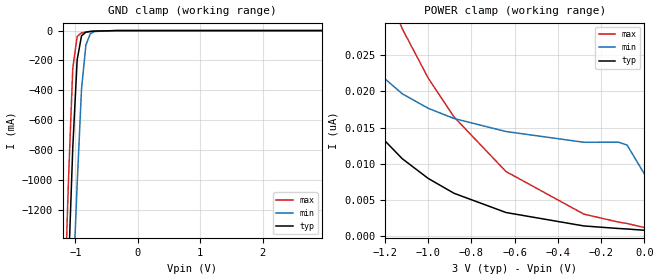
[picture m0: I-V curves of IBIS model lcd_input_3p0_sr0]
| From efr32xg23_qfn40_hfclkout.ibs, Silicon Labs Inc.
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|   Model lcd_input_3p0_sr0
[Model]  lcd_input_3p0_sr0
Model_type Input
C_comp   1.6300pF   1.4000pF   2.7000pF
[Temperature Range]   25.0000   0.1250k   -40.0000
[Pullup Reference]   3.0000V   2.7000V   3.3000V
[Pulldown Reference]   0.0V   0.0V   0.0V
[POWER Clamp Reference]   3.0000V   2.7000V   3.3000V
[GND Clamp Reference]   0.0V   0.0V   0.0V
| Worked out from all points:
|   GND clamp passes 1 mA (typ) near -0.56 V on its own axis
[GND_clamp]
|Voltage   I(typ)   I(min)   I(max)
-3V       -24.27A    -21.95A    -26.57A
-1.18V    -2.447A    -3.183A    -1.952A
-1.11V    -1.614A    -2.464A    -1.015A
-1.04V    -784mA     -1.746A    -252.8mA
-970mV    -196.2mA   -1.031A    -40.03mA
-900mV    -35mA      -390.7mA   -14.95mA
-830mV    -10.34mA   -96.94mA   -9.948mA
-760mV    -5.711mA   -21.43mA   -6.561mA
-690mV    -3.47mA    -6.05mA    -3.879mA
-340mV    -10.36uA   -45.49uA   -3.3uA
2.95V     657.9pA    12.89nA    538.5pA
[POWER_clamp]
|Voltage   I(typ)   I(min)   I(max)
-3V       338.2nA    9.288uA    587.2nA
-1.56V    29.18nA    39.44nA    70.52nA
-1.4V     20.57nA    28.74nA    51.74nA
-1.28V    15.63nA    23.83nA    40.5nA
-1.12V    10.68nA    19.68nA    28.7nA
-1V       7.945nA    17.67nA    21.86nA
-880mV    5.879nA    16.25nA    16.45nA
-640mV    3.219nA    14.45nA    8.897nA
-280mV    1.357nA    12.96nA    2.997nA
-120mV    1.003nA    12.97nA    1.894nA
-80mV     936.4pA    12.58nA    1.698nA
0V        757.3pA    8.576nA    1.134nA
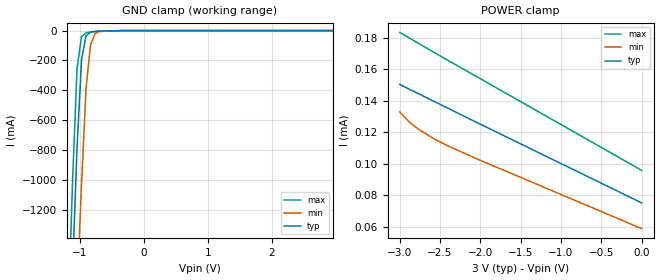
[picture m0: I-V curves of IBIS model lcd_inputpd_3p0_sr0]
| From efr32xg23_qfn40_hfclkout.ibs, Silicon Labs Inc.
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|   Model lcd_inputpd_3p0_sr0
[Model]  lcd_inputpd_3p0_sr0
Model_type Input
C_comp   1.6300pF   1.4000pF   2.7000pF
[Temperature Range]   25.0000   0.1250k   -40.0000
[Pullup Reference]   3.0000V   2.7000V   3.3000V
[Pulldown Reference]   0.0V   0.0V   0.0V
[POWER Clamp Reference]   3.0000V   2.7000V   3.3000V
[GND Clamp Reference]   0.0V   0.0V   0.0V
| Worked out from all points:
|   GND clamp passes 1 mA (typ) near -0.56 V on its own axis
[GND_clamp]
|Voltage   I(typ)   I(min)   I(max)
-3V       -24.27A    -21.95A    -26.57A
-1.18V    -2.447A    -3.183A    -1.952A
-1.11V    -1.614A    -2.464A    -1.015A
-1.04V    -784mA     -1.746A    -252.8mA
-970mV    -196.2mA   -1.031A    -40.04mA
-900mV    -35.01mA   -390.8mA   -14.96mA
-830mV    -10.35mA   -96.95mA   -9.963mA
-760mV    -5.723mA   -21.44mA   -6.576mA
-690mV    -3.482mA   -6.059mA   -3.893mA
-340mV    -18.62uA   -52.31uA   -13.01uA
2.95V     73.77uA    64.09uA    85.54uA
[POWER_clamp]
|Voltage   I(typ)   I(min)   I(max)
-3V       150.3uA    132.8uA    183.3uA
-2.88V    147.2uA    126.3uA    179.7uA
-2.76V    144.2uA    121.5uA    176.1uA
-2.56V    139.1uA    115.3uA    170.2uA
-2.4V     135.1uA    111.2uA    165.5uA
-2.08V    127uA      103.8uA    156.2uA
0V        75.02uA    58.67uA    95.69uA
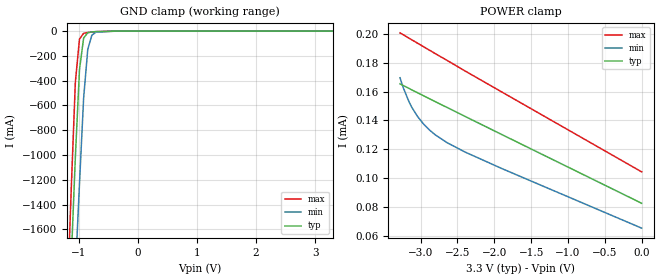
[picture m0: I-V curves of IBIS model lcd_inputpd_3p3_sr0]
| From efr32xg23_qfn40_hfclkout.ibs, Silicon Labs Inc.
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|   Model lcd_inputpd_3p3_sr0
[Model]  lcd_inputpd_3p3_sr0
Model_type Input
C_comp   1.6300pF   1.4000pF   2.7000pF
[Temperature Range]   25.0000   0.1250k   -40.0000
[Pullup Reference]   3.3000V   3.0000V   3.6000V
[Pulldown Reference]   0.0V   0.0V   0.0V
[POWER Clamp Reference]   3.3000V   3.0000V   3.6000V
[GND Clamp Reference]   0.0V   0.0V   0.0V
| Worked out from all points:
|   GND clamp passes 1 mA (typ) near -0.56 V on its own axis
[GND_clamp]
|Voltage   I(typ)   I(min)   I(max)
-3.3V     -27.87A    -25.05A    -30.64A
-1.2V     -2.686A    -3.389A    -2.22A
-1.13V    -1.852A    -2.669A    -1.282A
-1.06V    -1.021A    -1.951A    -413.8mA
-990mV    -311.8mA   -1.235A    -64.73mA
-920mV    -56.27mA   -542.5mA   -17.81mA
-850mV    -13.46mA   -148.6mA   -11.1mA
-780mV    -6.603mA   -32.69mA   -7.471mA
-710mV    -4.041mA   -8.332mA   -4.588mA
-360mV    -27.55uA   -77.14uA   -17.02uA
3.3V      82.64uA    71.93uA    95.72uA
[POWER_clamp]
|Voltage   I(typ)   I(min)   I(max)
-3.28V    165.4uA    169.6uA    200.7uA
-3.24V    164.3uA    163.2uA    199.5uA
-3.16V    162.3uA    153.2uA    197.1uA
-3.12V    161.2uA    149.1uA    195.9uA
-3.04V    159.2uA    142.6uA    193.5uA
-2.96V    157.1uA    137.5uA    191.1uA
-2.88V    155.1uA    133.4uA    188.7uA
-2.8V     153uA      130uA      186.3uA
-2.64V    149uA      124.6uA    181.6uA
-2.4V     142.9uA    118.2uA    174.4uA
-1.88V    129.8uA    106.3uA    159.2uA
0V        82.64uA    65.4uA     104.4uA
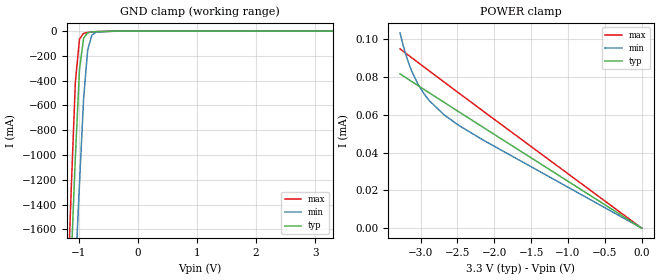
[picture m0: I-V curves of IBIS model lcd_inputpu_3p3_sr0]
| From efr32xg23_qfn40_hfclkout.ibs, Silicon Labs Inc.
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|   Model lcd_inputpu_3p3_sr0
[Model]  lcd_inputpu_3p3_sr0
Model_type Input
C_comp   1.6300pF   1.4000pF   2.7000pF
[Temperature Range]   25.0000   0.1250k   -40.0000
[Pullup Reference]   3.3000V   3.0000V   3.6000V
[Pulldown Reference]   0.0V   0.0V   0.0V
[POWER Clamp Reference]   3.3000V   3.0000V   3.6000V
[GND Clamp Reference]   0.0V   0.0V   0.0V
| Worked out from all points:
|   GND clamp passes 1 mA (typ) near -0.55 V on its own axis
[GND_clamp]
|Voltage   I(typ)   I(min)   I(max)
-3.3V     -27.87A    -25.05A    -30.64A
-1.2V     -2.686A    -3.389A    -2.22A
-1.13V    -1.852A    -2.669A    -1.282A
-1.06V    -1.021A    -1.951A    -413.9mA
-990mV    -311.9mA   -1.235A    -64.84mA
-920mV    -56.35mA   -542.5mA   -17.92mA
-850mV    -13.55mA   -148.6mA   -11.2mA
-780mV    -6.685mA   -32.76mA   -7.575mA
-710mV    -4.123mA   -8.397mA   -4.692mA
-360mV    -109.6uA   -142.3uA   -120.6uA
3.3V      1.052nA    6.53uA     -8.645uA
[POWER_clamp]
|Voltage   I(typ)   I(min)   I(max)
-3.28V    81.7uA     103.4uA    94.94uA
-3.24V    80.68uA    97.09uA    93.76uA
-3.2V     79.66uA    91.69uA    92.58uA
-3.16V    78.64uA    87.06uA    91.4uA
-3.12V    77.62uA    83.05uA    90.22uA
-3.04V    75.6uA     76.51uA    87.87uA
-2.96V    73.59uA    71.45uA    85.52uA
-2.88V    71.58uA    67.4uA     83.18uA
-2.68V    66.57uA    59.94uA    77.33uA
-2.48V    61.58uA    54.37uA    71.5uA
-2.16V    53.61uA    46.83uA    62.22uA
0V        1.052nA    8.934nA    2.227nA
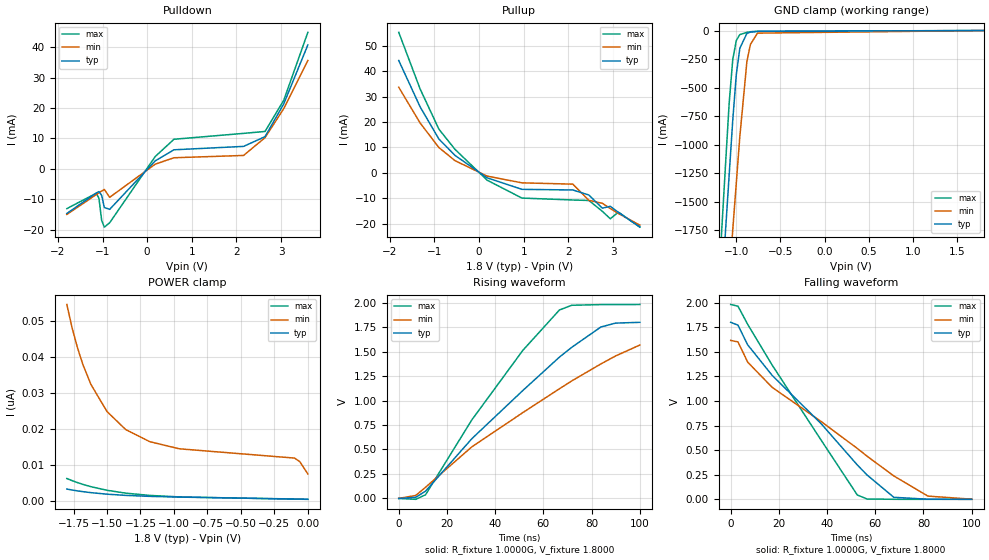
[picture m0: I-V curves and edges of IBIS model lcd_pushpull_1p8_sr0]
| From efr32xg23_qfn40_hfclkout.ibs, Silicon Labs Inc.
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|   Model lcd_pushpull_1p8_sr0
[Model]  lcd_pushpull_1p8_sr0
Model_type 3-state
Polarity   Non-Inverting
Enable   Active-High
C_comp   1.6300pF   1.4000pF   2.7000pF
[Temperature Range]   25.0000   0.1250k   -40.0000
[Pullup Reference]   1.8000V   1.6200V   1.9800V
[Pulldown Reference]   0.0V   0.0V   0.0V
[POWER Clamp Reference]   1.8000V   1.6200V   1.9800V
[GND Clamp Reference]   0.0V   0.0V   0.0V
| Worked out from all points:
|   slope of the pulldown table from 0 to 0.27 V, typ, clamps not added: 73.7 ohm
|   slope of the pullup table from 0 to 0.27 V, typ, clamps not added: 94.5 ohm
|   GND clamp passes 1 mA (typ) near -0.56 V on its own axis
|   rising waveform, R_fixture 1.0000G, V_fixture 1.8000: 20-80 % time 44.8ns typ, 55.5ns min, 33.5ns max; typ from 0 V to 1.8 V
|   falling waveform, R_fixture 1.0000G, V_fixture 1.8000: 20-80 % time 41.1ns typ, 52.2ns min, 30.7ns max; typ from 1.8 V to 0 V
[Pulldown]
|Voltage   I(typ)   I(min)   I(max)
-1.8V     -14.7mA    -15.01mA   -13.1mA
-1.14V    -7.95mA    -8.476mA   -8.033mA
-1.08V    -7.493mA   -7.885mA   -9.701mA
-1.02V    -8.713mA   -7.306mA   -16.93mA
-960mV    -12.74mA   -6.774mA   -19.2mA
-840mV    -13.34mA   -9.372mA   -17.75mA
180mV     2.62mA     1.539mA    4.045mA
600mV     6.272mA    3.652mA    9.739mA
2.16V     7.393mA    4.409mA    11.68mA
2.64V     10.59mA    10.27mA    12.31mA
3.06V     21.4mA     19.84mA    22.59mA
3.6V      40.81mA    35.67mA    44.95mA
[Pullup]
|Voltage   I(typ)   I(min)   I(max)
-1.8V     44.26mA    33.72mA    55.37mA
-1.32V    25.95mA    19.61mA    32.99mA
-900mV    13.3mA     9.934mA    17.18mA
-540mV    6.86mA     4.786mA    9.239mA
180mV     -2.006mA   -1.315mA   -2.92mA
960mV     -6.533mA   -3.97mA    -9.976mA
2.1V      -6.782mA   -4.481mA   -10.73mA
2.46V     -8.779mA   -10.88mA   -10.92mA
2.76V     -13.95mA   -12.02mA   -15.17mA
2.94V     -13.22mA   -14.09mA   -18.14mA
3.12V     -15.62mA   -16.06mA   -15.5mA
3.6V      -21.33mA   -20.63mA   -21.44mA
[GND_clamp]
|Voltage   I(typ)   I(min)   I(max)
-1.8V     -9.867A    -9.569A    -10.32A
-1.2V     -2.688A    -3.389A    -2.223A
-1.16V    -2.211A    -2.978A    -1.687A
-1.12V    -1.735A    -2.567A    -1.152A
-1.08V    -1.26A     -2.157A    -630.3mA
-1.04V    -786.2mA   -1.747A    -256.2mA
-1V       -388.1mA   -1.338A    -87.58mA
-960mV    -155.8mA   -930mA     -35.74mA
-880mV    -25.03mA   -272.7mA   -16.29mA
-840mV    -13.92mA   -121.5mA   -10.46mA
-760mV    -7.819mA   -22.78mA   -6.532mA
1.8V      420.7pA    11.94nA    334.2pA
[POWER_clamp]
|Voltage   I(typ)   I(min)   I(max)
-1.8V     3.26nA     54.56nA    6.193nA
-1.76V    2.991nA    47.98nA    5.591nA
-1.72V    2.751nA    42.48nA    5.048nA
-1.68V    2.538nA    37.87nA    4.559nA
-1.62V    2.261nA    32.33nA    3.919nA
-1.5V     1.836nA    24.81nA    2.92nA
-1.36V    1.5nA      19.78nA    2.12nA
-1.18V    1.228nA    16.42nA    1.491nA
-960mV    1.023nA    14.45nA    1.076nA
-100mV    499.2pA    11.87nA    445.7pA
-60mV     472.6pA    10.86nA    433.4pA
0V        420.7pA    7.448nA    403.8pA
[Ramp]
| variable   typ   min   max
dV/dt_r  1.0333/48.1802n   0.8058/54.3189n   1.1719/36.3741n
dV/dt_f  1.0636/46.4446n   0.9166/59.9076n   1.1807/33.5893n
R_load = 10.0000k
[Rising Waveform]
R_fixture= 1.0000G
V_fixture= 1.8000
V_fixture_min= 1.6200
V_fixture_max= 1.9800
|time   V(typ)   V(min)   V(max)
0s        347uV      809.6uV    128.9uV
7.071ns   12.12mV    31.05mV    -8.769mV
11.11ns   74.53mV    114.2mV    37.75mV
30.3ns    609.7mV    526.6mV    801.3mV
51.52ns   1.103V     877.3mV    1.513V
66.67ns   1.443V     1.12V      1.924V
71.72ns   1.542V     1.199V     1.972V
83.84ns   1.75V      1.373V     1.979V
89.9ns    1.79V      1.454V     1.979V
100ns     1.798V     1.566V     1.98V
[Falling Waveform]
R_fixture= 1.0000G
V_fixture= 1.8000
V_fixture_min= 1.6200
V_fixture_max= 1.9800
|time   V(typ)   V(min)   V(max)
0s        1.799V     1.615V     1.98V
3.03ns    1.77V      1.6V       1.963V
7.071ns   1.57V      1.394V     1.778V
17.17ns   1.261V     1.139V     1.366V
37.37ns   773.3mV    793.6mV    607.7mV
52.53ns   349.9mV    517.6mV    44.53mV
56.57ns   247.8mV    439mV      3.564mV
67.68ns   20.81mV    238.1mV    555.3uV
81.82ns   1.007mV    33.01mV    259.7uV
100ns     383.8uV    1.598mV    130.2uV
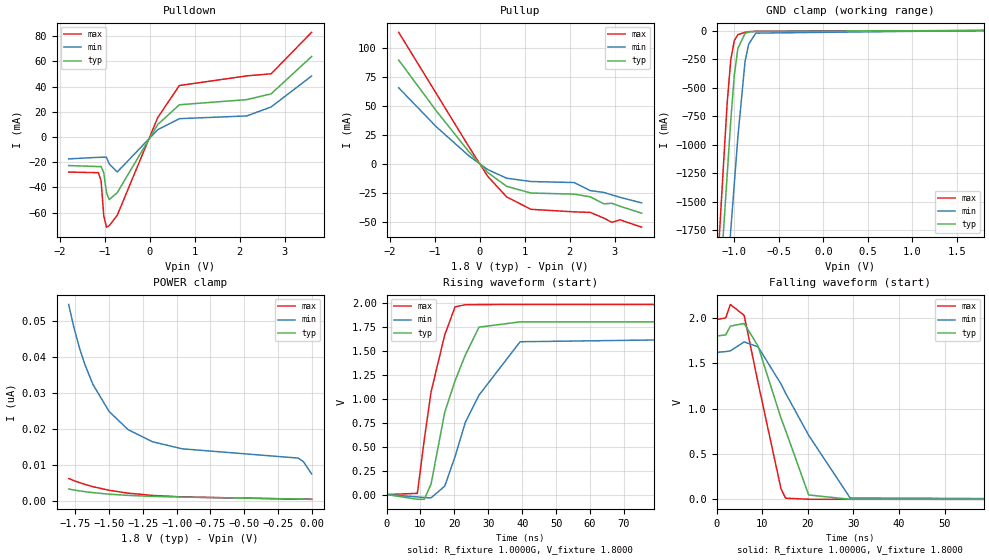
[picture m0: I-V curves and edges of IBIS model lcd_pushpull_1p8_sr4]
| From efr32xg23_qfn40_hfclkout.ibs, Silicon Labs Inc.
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|   Model lcd_pushpull_1p8_sr4
[Model]  lcd_pushpull_1p8_sr4
Model_type 3-state
Polarity   Non-Inverting
Enable   Active-High
C_comp   1.6300pF   1.4000pF   2.7000pF
[Temperature Range]   25.0000   0.1250k   -40.0000
[Pullup Reference]   1.8000V   1.6200V   1.9800V
[Pulldown Reference]   0.0V   0.0V   0.0V
[POWER Clamp Reference]   1.8000V   1.6200V   1.9800V
[GND Clamp Reference]   0.0V   0.0V   0.0V
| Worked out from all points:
|   slope of the pulldown table from 0 to 0.27 V, typ, clamps not added: 19.4 ohm
|   slope of the pullup table from 0 to 0.27 V, typ, clamps not added: 26.3 ohm
|   GND clamp passes 1 mA (typ) near -0.56 V on its own axis
|   rising waveform, R_fixture 1.0000G, V_fixture 1.8000: 20-80 % time 8.5ns typ, 12.4ns min, 5.99ns max; typ from 0 V to 1.8 V
|   falling waveform, R_fixture 1.0000G, V_fixture 1.8000: 20-80 % time 7.02ns typ, 10.4ns min, 4.86ns max; typ from 1.8 V to 0 V
[Pulldown]
|Voltage   I(typ)   I(min)   I(max)
-1.8V     -22.72mA   -17.46mA   -27.89mA
-1.14V    -23.53mA   -16.18mA   -28.38mA
-1.08V    -23.42mA   -16.18mA   -34.7mA
-1.02V    -28.53mA   -16.15mA   -62.46mA
-960mV    -44.06mA   -16.13mA   -71.6mA
-900mV    -49.75mA   -21.38mA   -70.47mA
-720mV    -44.21mA   -27.82mA   -62.15mA
180mV     9.861mA    5.736mA    15.36mA
660mV     25.51mA    14.47mA    40.77mA
2.16V     29.61mA    16.66mA    48.44mA
2.7V      34.16mA    23.78mA    50.07mA
3.6V      63.79mA    48.31mA    82.99mA
[Pullup]
|Voltage   I(typ)   I(min)   I(max)
-1.8V     89.55mA    65.7mA     113.4mA
-960mV    45.65mA    32.03mA    60.52mA
-240mV    10.71mA    7.201mA    15.05mA
180mV     -7.21mA    -4.712mA   -10.49mA
600mV     -19.07mA   -12.08mA   -28.15mA
1.14V     -24.85mA   -14.93mA   -38.85mA
2.1V      -25.76mA   -15.8mA    -41.02mA
2.46V     -28.12mA   -22.77mA   -41.5mA
2.76V     -34.11mA   -24.28mA   -46.4mA
2.94V     -33.67mA   -26.45mA   -50.04mA
3.12V     -36.21mA   -28.52mA   -47.86mA
3.6V      -42.18mA   -33.32mA   -54.18mA
[GND_clamp]
|Voltage   I(typ)   I(min)   I(max)
-1.8V     -9.867A    -9.569A    -10.32A
-1.2V     -2.688A    -3.389A    -2.223A
-1.16V    -2.211A    -2.978A    -1.687A
-1.12V    -1.735A    -2.567A    -1.152A
-1.08V    -1.26A     -2.157A    -630.3mA
-1.04V    -786.2mA   -1.747A    -256.2mA
-1V       -388.1mA   -1.338A    -87.58mA
-960mV    -155.8mA   -930mA     -35.74mA
-880mV    -25.03mA   -272.7mA   -16.29mA
-840mV    -13.92mA   -121.5mA   -10.46mA
-760mV    -7.819mA   -22.78mA   -6.532mA
1.8V      420.7pA    11.94nA    334.2pA
[POWER_clamp]
|Voltage   I(typ)   I(min)   I(max)
-1.8V     3.26nA     54.56nA    6.193nA
-1.76V    2.991nA    47.98nA    5.591nA
-1.72V    2.751nA    42.48nA    5.048nA
-1.68V    2.538nA    37.87nA    4.559nA
-1.62V    2.261nA    32.33nA    3.919nA
-1.5V     1.836nA    24.81nA    2.92nA
-1.36V    1.5nA      19.78nA    2.12nA
-1.18V    1.228nA    16.42nA    1.491nA
-960mV    1.023nA    14.45nA    1.076nA
-100mV    499.2pA    11.87nA    445.7pA
-60mV     472.6pA    10.86nA    433.4pA
0V        420.7pA    7.448nA    403.8pA
[Ramp]
| variable   typ   min   max
dV/dt_r  1.0772/9.0593n   0.9679/13.5624n   1.1859/6.2617n
dV/dt_f  1.0782/7.3523n   0.9692/11.1155n   1.1867/5.0016n
R_load = 10.0000k
[Rising Waveform]
R_fixture= 1.0000G
V_fixture= 1.8000
V_fixture_min= 1.6200
V_fixture_max= 1.9800
|time   V(typ)   V(min)   V(max)
0s        6.707uV    22.16uV    2.837uV
9.091ns   -49.63mV   -24.87mV   12.25mV
11.11ns   -49.96mV   -31.4mV    567mV
13.13ns   108.3mV    -34.57mV   1.069V
17.17ns   858.5mV    87.45mV    1.664V
20.2ns    1.185V     394.7mV    1.955V
23.23ns   1.453V     751.7mV    1.978V
27.27ns   1.744V     1.036V     1.979V
39.39ns   1.799V     1.592V     1.98V
100ns     1.8V       1.62V      1.98V
[Falling Waveform]
R_fixture= 1.0000G
V_fixture= 1.8000
V_fixture_min= 1.6200
V_fixture_max= 1.9800
|time   V(typ)   V(min)   V(max)
0s        1.8V       1.62V      1.98V
2.02ns    1.812V     1.628V     2V
3.03ns    1.909V     1.636V     2.147V
6.061ns   1.938V     1.735V     2.027V
9.091ns   1.69V      1.681V     1.288V
14.14ns   893.2mV    1.271V     114.9mV
15.15ns   758.6mV    1.169V     12.83mV
20.2ns    47.98mV    705.9mV    510.2uV
29.29ns   507.4uV    15.11mV    137.5uV
100ns     6.843uV    22.31uV    2.847uV
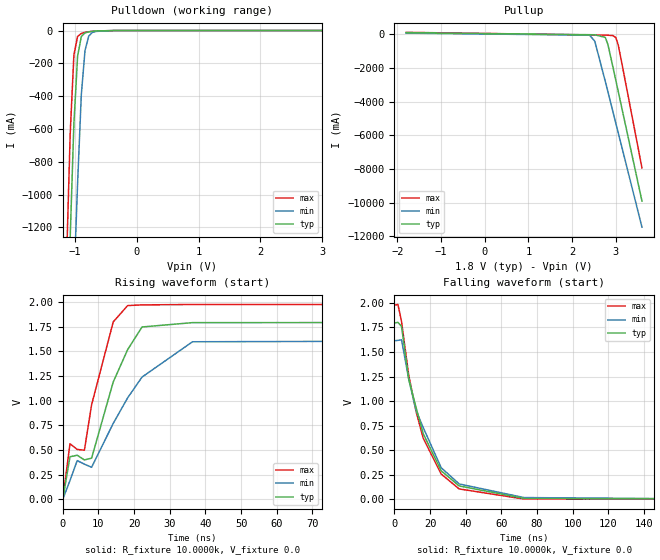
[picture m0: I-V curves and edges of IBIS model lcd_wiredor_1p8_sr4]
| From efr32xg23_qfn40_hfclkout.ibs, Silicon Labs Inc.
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|   Model lcd_wiredor_1p8_sr4
[Model]  lcd_wiredor_1p8_sr4
Model_type Output
Polarity   Non-Inverting
Enable   Active-Low
C_comp   1.6300pF   1.4000pF   2.7000pF
[Temperature Range]   25.0000   0.1250k   -40.0000
[Pullup Reference]   1.8000V   1.6200V   1.9800V
[Pulldown Reference]   0.0V   0.0V   0.0V
[POWER Clamp Reference]   1.8000V   1.6200V   1.9800V
[GND Clamp Reference]   0.0V   0.0V   0.0V
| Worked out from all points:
|   slope of the pullup table from 0 to 0.27 V, typ, clamps not added: 26.3 ohm
|   rising waveform, R_fixture 10.0000k, V_fixture 0.0: 20-80 % time 15.4ns typ, 20ns min, 10.9ns max; typ from 0 V to 1.79 V
|   falling waveform, R_fixture 10.0000k, V_fixture 0.0: 20-80 % time 17.3ns typ, 18.7ns min, 15.9ns max; typ from 1.8 V to 0 V
[Pulldown]
|Voltage   I(typ)   I(min)   I(max)
-1.8V     -9.867A    -9.569A    -10.32A
-1.14V    -1.973A    -2.773A    -1.419A
-1.08V    -1.26A     -2.157A    -630.4mA
-1.02V    -568mA     -1.543A    -149.7mA
-960mV    -155.8mA   -930mA     -35.74mA
-900mV    -37.3mA    -392mA     -18.17mA
-840mV    -13.92mA   -121.5mA   -10.46mA
-780mV    -8.725mA   -34.03mA   -7.422mA
-720mV    -4.294mA   -11.21mA   -4.92mA
-660mV    -2.711mA   -5.267mA   -2.939mA
-360mV    -18.79uA   -69.64uA   -6.715uA
3.6V      3.264nA    104.4nA    3.919nA
[Pullup]
|Voltage   I(typ)   I(min)   I(max)
-1.8V     89.55mA    65.7mA     113.4mA
2.4V      -28.79mA   -55.09mA   -41.35mA
2.52V     -33.4mA    -414.8mA   -42.59mA
2.76V     -189.9mA   -2.797A    -53.83mA
2.82V     -601mA     -3.414A    -58.12mA
2.94V     -2.006A    -4.65A     -82.38mA
3V        -2.722A    -5.268A    -196.6mA
3.06V     -3.439A    -5.887A    -675.1mA
3.12V     -4.156A    -6.505A    -1.464A
3.24V     -5.593A    -7.743A    -3.076A
3.3V      -6.312A    -8.362A    -3.885A
3.6V      -9.909A    -11.46A    -7.939A
[Ramp]
| variable   typ   min   max
dV/dt_r  1.0773/15.4419n   0.9682/19.9658n   1.1859/10.8682n
dV/dt_f  47.8332u/2.7967p   38.5697u/5.0330p   85.2176u/2.8246p
R_load = 10.0000k
[Rising Waveform]
R_fixture= 10.0000k
V_fixture= 0.0
V_fixture_min= 0.0
V_fixture_max= 0.0
|time   V(typ)   V(min)   V(max)
0s        3.312uV    55.57uV    2.87uV
2.02ns    431.5mV    190.6mV    564mV
4.04ns    447.3mV    392.9mV    505.8mV
6.061ns   399.6mV    356.7mV    498.5mV
8.081ns   417.6mV    325.2mV    958.9mV
14.14ns   1.19V      769.9mV    1.799V
18.18ns   1.518V     1.029V     1.965V
22.22ns   1.748V     1.24V      1.972V
36.36ns   1.792V     1.598V     1.976V
200ns     1.795V     1.614V     1.976V
[Falling Waveform]
R_fixture= 10.0000k
V_fixture= 0.0
V_fixture_min= 0.0
V_fixture_max= 0.0
|time   V(typ)   V(min)   V(max)
0s        1.796V     1.614V     1.977V
2.02ns    1.802V     1.619V     1.984V
4.04ns    1.761V     1.624V     1.809V
8.081ns   1.224V     1.222V     1.262V
12.12ns   938.8mV    906.8mV    899mV
16.16ns   669.5mV    732.2mV    623.1mV
26.26ns   290.1mV    321.8mV    257.2mV
36.36ns   135.8mV    156.1mV    105.4mV
72.73ns   8.787mV    17.35mV    2.315mV
200ns     -102.6uV   786.2uV    -490.8uV
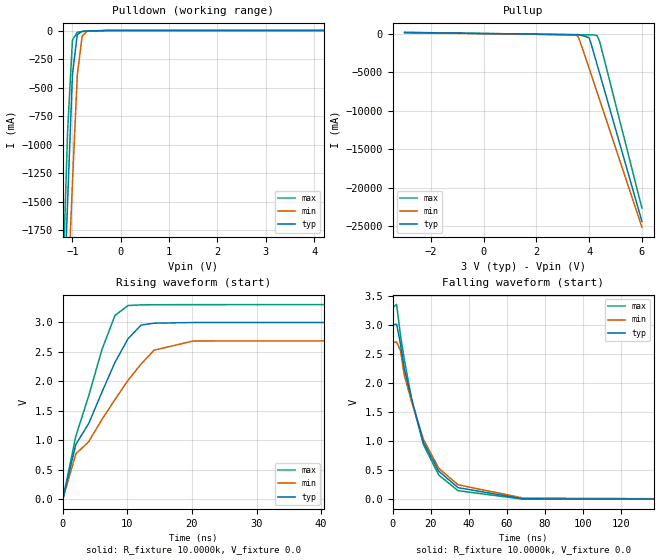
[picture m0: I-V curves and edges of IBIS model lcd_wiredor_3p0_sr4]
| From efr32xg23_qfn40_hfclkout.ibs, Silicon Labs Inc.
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|   Model lcd_wiredor_3p0_sr4
[Model]  lcd_wiredor_3p0_sr4
Model_type Output
Polarity   Non-Inverting
Enable   Active-Low
C_comp   1.6300pF   1.4000pF   2.7000pF
[Temperature Range]   25.0000   0.1250k   -40.0000
[Pullup Reference]   3.0000V   2.7000V   3.3000V
[Pulldown Reference]   0.0V   0.0V   0.0V
[POWER Clamp Reference]   3.0000V   2.7000V   3.3000V
[GND Clamp Reference]   0.0V   0.0V   0.0V
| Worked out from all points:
|   slope of the pullup table from 0 to 0.45 V, typ, clamps not added: 16.9 ohm
|   rising waveform, R_fixture 10.0000k, V_fixture 0.0: 20-80 % time 7.17ns typ, 9.72ns min, 5.18ns max; typ from 0 V to 3 V
|   falling waveform, R_fixture 10.0000k, V_fixture 0.0: 20-80 % time 16.5ns typ, 18.1ns min, 14.8ns max; typ from 3 V to 0 V
[Pulldown]
|Voltage   I(typ)   I(min)   I(max)
-3V       -24.27A    -21.95A    -26.57A
-1.2V     -2.686A    -3.389A    -2.22A
-1.1V     -1.495A    -2.361A    -881.8mA
-1V       -385.8mA   -1.337A    -84.19mA
-900mV    -34.99mA   -390.7mA   -14.95mA
-800mV    -7.703mA   -50.4mA    -8.403mA
-700mV    -3.742mA   -7.062mA   -4.219mA
-300mV    -2.847uA   -17.98uA   -692.6nA
6V        338.2nA    35.99uA    408.8nA
[Pullup]
|Voltage   I(typ)   I(min)   I(max)
-3V       194.2mA    164.1mA    218.3mA
3.5V      -78.04mA   -106.9mA   -111.5mA
3.6V      -80.27mA   -448.8mA   -111.7mA
4V        -471.9mA   -4.48A     -119.8mA
4.1V      -1.581A    -5.511A    -126.2mA
4.2V      -2.773A    -6.543A    -134.9mA
4.3V      -3.971A    -7.574A    -205.9mA
4.4V      -5.168A    -8.607A    -1.001A
4.5V      -6.366A    -9.639A    -2.34A
4.7V      -8.765A    -11.71A    -5.039A
4.8V      -9.964A    -12.74A    -6.39A
6V        -24.38A    -25.14A    -22.65A
[Ramp]
| variable   typ   min   max
dV/dt_r  1.7971/7.1745n   1.6163/9.7176n   1.9776/5.1781n
dV/dt_f  0.1145m/6.6608p   65.9331u/5.4080p   0.2003m/5.3495p
R_load = 10.0000k
[Rising Waveform]
R_fixture= 10.0000k
V_fixture= 0.0
V_fixture_min= 0.0
V_fixture_max= 0.0
|time   V(typ)   V(min)   V(max)
0s        4.624uV    47.91uV    4.748uV
2.02ns    929mV      768mV      1.068V
4.04ns    1.288V     979.6mV    1.761V
6.061ns   1.813V     1.352V     2.532V
8.081ns   2.318V     1.687V     3.112V
10.1ns    2.716V     2.014V     3.279V
12.12ns   2.947V     2.289V     3.289V
14.14ns   2.98V      2.523V     3.292V
20.2ns    2.991V     2.679V     3.294V
200ns     2.995V     2.694V     3.296V
[Falling Waveform]
R_fixture= 10.0000k
V_fixture= 0.0
V_fixture_min= 0.0
V_fixture_max= 0.0
|time   V(typ)   V(min)   V(max)
0s        2.995V     2.694V     3.296V
2.02ns    3.01V      2.704V     3.347V
4.04ns    2.67V      2.557V     2.819V
6.061ns   2.24V      2.134V     2.406V
10.1ns    1.704V     1.655V     1.684V
16.16ns   975.7mV    1.029V     936mV
24.24ns   482.9mV    530.6mV    415.7mV
34.34ns   199.8mV    249.4mV    148.3mV
68.69ns   8.115mV    21.09mV    1.351mV
200ns     -452.2uV   289.4uV    -558.8uV
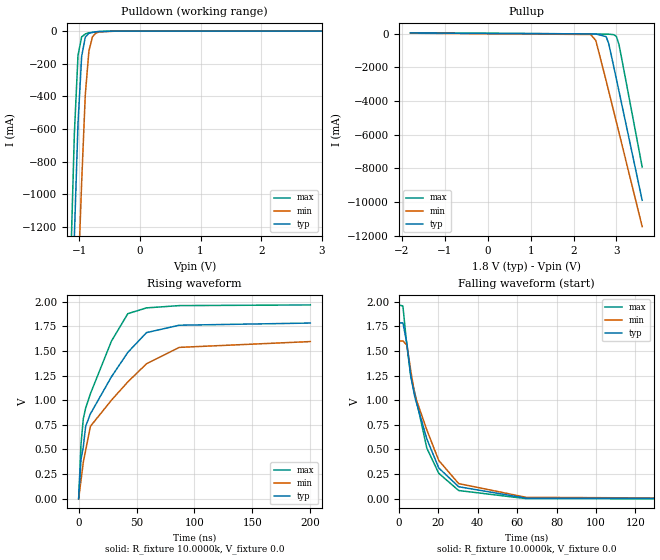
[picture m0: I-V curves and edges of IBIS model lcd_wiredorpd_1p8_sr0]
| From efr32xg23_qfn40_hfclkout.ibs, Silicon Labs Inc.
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|   Model lcd_wiredorpd_1p8_sr0
[Model]  lcd_wiredorpd_1p8_sr0
Model_type Output
Polarity   Non-Inverting
Enable   Active-Low
C_comp   1.6300pF   1.4000pF   2.7000pF
[Temperature Range]   25.0000   0.1250k   -40.0000
[Pullup Reference]   1.8000V   1.6200V   1.9800V
[Pulldown Reference]   0.0V   0.0V   0.0V
[POWER Clamp Reference]   1.8000V   1.6200V   1.9800V
[GND Clamp Reference]   0.0V   0.0V   0.0V
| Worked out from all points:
|   slope of the pulldown table from 0 to 0.27 V, typ, clamps not added: 40.6 kohm
|   slope of the pullup table from 0 to 0.27 V, typ, clamps not added: 94.5 ohm
|   rising waveform, R_fixture 10.0000k, V_fixture 0.0: 20-80 % time 37.1ns typ, 46.6ns min, 25.9ns max; typ from 0 V to 1.78 V
|   falling waveform, R_fixture 10.0000k, V_fixture 0.0: 20-80 % time 14ns typ, 15.9ns min, 12.5ns max; typ from 1.78 V to 0 V
[Pulldown]
|Voltage   I(typ)   I(min)   I(max)
-1.8V     -9.867A    -9.569A    -10.32A
-1.14V    -1.973A    -2.773A    -1.419A
-1.08V    -1.26A     -2.157A    -630.5mA
-1.02V    -568mA     -1.543A    -149.7mA
-960mV    -155.8mA   -930mA     -35.75mA
-900mV    -37.31mA   -392mA     -18.18mA
-840mV    -13.93mA   -121.5mA   -10.47mA
-780mV    -8.737mA   -34.04mA   -7.436mA
-720mV    -4.306mA   -11.22mA   -4.934mA
-660mV    -2.722mA   -5.276mA   -2.953mA
-360mV    -27.29uA   -76.51uA   -16.82uA
3.6V      88.26uA    75.14uA    103.4uA
[Pullup]
|Voltage   I(typ)   I(min)   I(max)
-1.8V     44.26mA    33.72mA    55.37mA
2.4V      -9.562mA   -43.33mA   -10.84mA
2.52V     -13.93mA   -402.8mA   -11.94mA
2.76V     -169.7mA   -2.785A    -22.6mA
2.82V     -580.7mA   -3.402A    -26.69mA
2.94V     -1.986A    -4.637A    -53.89mA
3V        -2.702A    -5.256A    -167.9mA
3.06V     -3.418A    -5.874A    -646.3mA
3.12V     -4.136A    -6.493A    -1.435A
3.24V     -5.572A    -7.731A    -3.047A
3.3V      -6.291A    -8.35A     -3.855A
3.6V      -9.889A    -11.45A    -7.908A
[Ramp]
| variable   typ   min   max
dV/dt_r  1.0697/37.0699n   0.9570/46.5903n   1.1803/25.8549n
dV/dt_f  0.2131/9.8036n   0.1690/11.4670n   0.2651/7.8311n
R_load = 10.0000k
[Rising Waveform]
R_fixture= 10.0000k
V_fixture= 0.0
V_fixture_min= 0.0
V_fixture_max= 0.0
|time   V(typ)   V(min)   V(max)
0s        2.578uV    44.87uV    2.149uV
2.02ns    397.7mV    185.1mV    553.4mV
4.04ns    528.4mV    373mV      813.5mV
6.061ns   736.8mV    491mV      920.7mV
10.1ns    860.4mV    733.8mV    1.064V
28.28ns   1.237V     1V         1.599V
42.42ns   1.485V     1.185V     1.878V
58.59ns   1.686V     1.37V      1.937V
86.87ns   1.761V     1.536V     1.96V
200ns     1.783V     1.595V     1.967V
[Falling Waveform]
R_fixture= 10.0000k
V_fixture= 0.0
V_fixture_min= 0.0
V_fixture_max= 0.0
|time   V(typ)   V(min)   V(max)
0s        1.785V     1.6V       1.968V
2.02ns    1.786V     1.603V     1.957V
4.04ns    1.577V     1.559V     1.553V
6.061ns   1.241V     1.295V     1.236V
8.081ns   1.032V     1.049V     1.073V
14.14ns   607.6mV    699.5mV    514.3mV
20.2ns    312.1mV    388.5mV    258.4mV
30.3ns    121.2mV    153.2mV    82.78mV
64.65ns   5.131mV    13.33mV    76.77uV
200ns     -87.29uV   582.2uV    -353.4uV
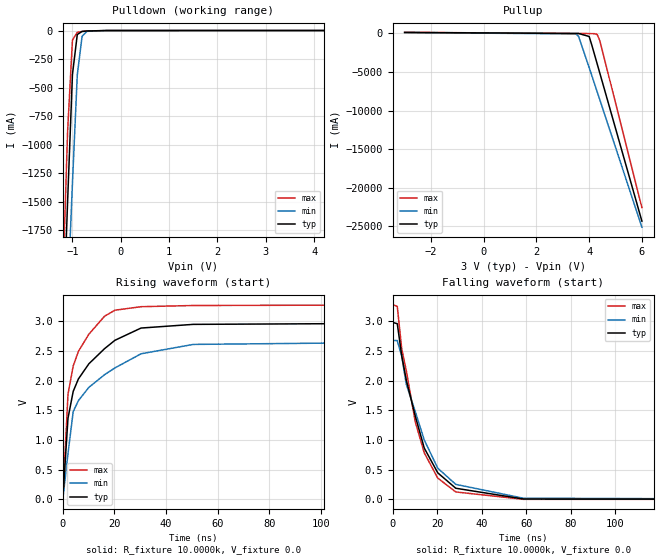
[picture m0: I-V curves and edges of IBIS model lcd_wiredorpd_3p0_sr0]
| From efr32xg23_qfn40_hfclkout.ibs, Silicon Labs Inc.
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|   Model lcd_wiredorpd_3p0_sr0
[Model]  lcd_wiredorpd_3p0_sr0
Model_type Output
Polarity   Non-Inverting
Enable   Active-Low
C_comp   1.6300pF   1.4000pF   2.7000pF
[Temperature Range]   25.0000   0.1250k   -40.0000
[Pullup Reference]   3.0000V   2.7000V   3.3000V
[Pulldown Reference]   0.0V   0.0V   0.0V
[POWER Clamp Reference]   3.0000V   2.7000V   3.3000V
[GND Clamp Reference]   0.0V   0.0V   0.0V
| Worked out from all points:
|   slope of the pulldown table from 0 to 0.45 V, typ, clamps not added: 40 kohm
|   slope of the pullup table from 0 to 0.45 V, typ, clamps not added: 61.2 ohm
|   rising waveform, R_fixture 10.0000k, V_fixture 0.0: 20-80 % time 11.4ns typ, 16.1ns min, 6.97ns max; typ from 0 V to 2.98 V
|   falling waveform, R_fixture 10.0000k, V_fixture 0.0: 20-80 % time 13.4ns typ, 14.8ns min, 11.8ns max; typ from 2.98 V to 0 V
[Pulldown]
|Voltage   I(typ)   I(min)   I(max)
-3V       -24.27A    -21.95A    -26.57A
-1.2V     -2.686A    -3.389A    -2.22A
-1.1V     -1.495A    -2.361A    -881.8mA
-1V       -385.8mA   -1.337A    -84.2mA
-900mV    -35.01mA   -390.8mA   -14.96mA
-800mV    -7.715mA   -50.41mA   -8.418mA
-700mV    -3.753mA   -7.071mA   -4.233mA
-300mV    -10.27uA   -24.2uA    -9.353uA
6V        150.3uA    165.9uA    174.4uA
[Pullup]
|Voltage   I(typ)   I(min)   I(max)
-3V       110.5mA    92.38mA    126.9mA
3.5V      -20.93mA   -70.49mA   -28.69mA
3.6V      -22.98mA   -412.2mA   -28.7mA
4V        -413.4mA   -4.443A    -35.97mA
4.1V      -1.522A    -5.474A    -42.03mA
4.2V      -2.714A    -6.505A    -50.3mA
4.3V      -3.912A    -7.537A    -120.8mA
4.4V      -5.109A    -8.569A    -915.3mA
4.5V      -6.307A    -9.602A    -2.255A
4.7V      -8.705A    -11.67A    -4.954A
4.8V      -9.905A    -12.7A     -6.304A
6V        -24.32A    -25.1A     -22.56A
[Ramp]
| variable   typ   min   max
dV/dt_r  1.7893/11.4345n   1.6058/16.1232n   1.9711/6.9728n
dV/dt_f  0.3602/8.6531n   0.2882/10.8504n   0.4453/7.7858n
R_load = 10.0000k
[Rising Waveform]
R_fixture= 10.0000k
V_fixture= 0.0
V_fixture_min= 0.0
V_fixture_max= 0.0
|time   V(typ)   V(min)   V(max)
0s        3.563uV    38.12uV    3.534uV
2.02ns    1.368V     771.5mV    1.773V
4.04ns    1.821V     1.479V     2.249V
6.061ns   2.031V     1.665V     2.496V
10.1ns    2.285V     1.888V     2.784V
16.16ns   2.54V      2.101V     3.087V
20.2ns    2.682V     2.216V     3.189V
30.3ns    2.888V     2.454V     3.248V
50.51ns   2.95V      2.612V     3.268V
200ns     2.982V     2.676V     3.285V
[Falling Waveform]
R_fixture= 10.0000k
V_fixture= 0.0
V_fixture_min= 0.0
V_fixture_max= 0.0
|time   V(typ)   V(min)   V(max)
0s        2.984V     2.679V     3.286V
2.02ns    2.962V     2.678V     3.253V
4.04ns    2.416V     2.409V     2.533V
6.061ns   2.013V     1.941V     2.172V
10.1ns    1.403V     1.479V     1.306V
14.14ns   863.8mV    1V         783.3mV
20.2ns    446.2mV    524.6mV    357.6mV
28.28ns   186.3mV    251.8mV    124mV
58.59ns   5.314mV    18.58mV    -604.8uV
200ns     -336.5uV   209.9uV    -398.3uV
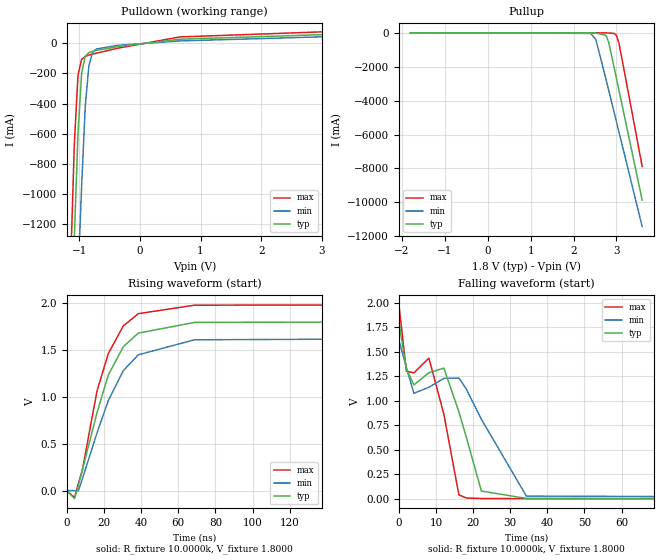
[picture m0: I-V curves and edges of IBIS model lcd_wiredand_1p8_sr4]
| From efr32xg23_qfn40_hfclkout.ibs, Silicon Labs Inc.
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|   Model lcd_wiredand_1p8_sr4
[Model]  lcd_wiredand_1p8_sr4
Model_type Output
Polarity   Inverting
Enable   Active-Low
C_comp   1.6300pF   1.4000pF   2.7000pF
[Temperature Range]   25.0000   0.1250k   -40.0000
[Pullup Reference]   1.8000V   1.6200V   1.9800V
[Pulldown Reference]   0.0V   0.0V   0.0V
[POWER Clamp Reference]   1.8000V   1.6200V   1.9800V
[GND Clamp Reference]   0.0V   0.0V   0.0V
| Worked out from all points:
|   slope of the pulldown table from 0 to 0.27 V, typ, clamps not added: 19.4 ohm
|   rising waveform, R_fixture 10.0000k, V_fixture 1.8000: 20-80 % time 16.8ns typ, 19.9ns min, 15ns max; typ from 0.003 V to 1.8 V
|   falling waveform, R_fixture 10.0000k, V_fixture 1.8000: 20-80 % time 18.4ns typ, 25.6ns min, 12.9ns max; typ from 1.8 V to 0.003 V
[Pulldown]
|Voltage   I(typ)   I(min)   I(max)
-1.8V     -9.89A     -9.587A    -10.35A
-1.14V    -1.996A    -2.789A    -1.448A
-1.08V    -1.283A    -2.173A    -665.1mA
-1.02V    -596.5mA   -1.559A    -212.1mA
-960mV    -199.8mA   -946.1mA   -107.3mA
-900mV    -87.05mA   -413.4mA   -88.64mA
-840mV    -62.82mA   -148.8mA   -78.59mA
-780mV    -55.48mA   -62.77mA   -72.78mA
-720mV    -48.51mA   -39.03mA   -67.07mA
-360mV    -23.12mA   -14.48mA   -33.62mA
660mV     25.51mA    14.47mA    40.77mA
3.6V      63.79mA    48.31mA    82.99mA
[Pullup]
|Voltage   I(typ)   I(min)   I(max)
-1.8V     3.264nA    54.56nA    6.193nA
2.4V      -1.548mA   -34.03mA   -47.22uA
2.52V     -4.294mA   -392mA     -642.2uA
2.76V     -155.8mA   -2.773A    -7.422mA
2.82V     -568mA     -3.389A    -10.46mA
2.94V     -1.973A    -4.623A    -32.35mA
3V        -2.688A    -5.241A    -146.2mA
3.06V     -3.403A    -5.859A    -626.9mA
3.12V     -4.12A     -6.477A    -1.416A
3.24V     -5.555A    -7.713A    -3.027A
3.3V      -6.273A    -8.332A    -3.835A
3.6V      -9.867A    -11.43A    -7.885A
[Ramp]
| variable   typ   min   max
dV/dt_r  -0.1667m/69.1013p   -0.1910m/0.1545n   -0.1300m/15.2276p
dV/dt_f  1.0782/18.3801n   0.9692/25.6197n   1.1867/12.9397n
R_load = 10.0000k
[Rising Waveform]
R_fixture= 10.0000k
V_fixture= 1.8000
V_fixture_min= 1.6200
V_fixture_max= 1.9800
|time   V(typ)   V(min)   V(max)
0s        2.931mV    4.511mV    2.082mV
4.04ns    -82.31mV   3.552mV    -71.02mV
6.061ns   57.51mV    -576.7uV   77.69mV
8.081ns   211.7mV    119.1mV    208.1mV
16.16ns   834.7mV    619.6mV    1.066V
22.22ns   1.234V     960.8mV    1.462V
30.3ns    1.535V     1.28V      1.756V
38.38ns   1.68V      1.449V     1.887V
68.69ns   1.794V     1.609V     1.977V
200ns     1.8V       1.62V      1.98V
[Falling Waveform]
R_fixture= 10.0000k
V_fixture= 1.8000
V_fixture_min= 1.6200
V_fixture_max= 1.9800
|time   V(typ)   V(min)   V(max)
0s        1.8V       1.62V      1.98V
2.02ns    1.327V     1.337V     1.303V
4.04ns    1.164V     1.078V     1.286V
8.081ns   1.288V     1.14V      1.437V
12.12ns   1.335V     1.23V      863.7mV
16.16ns   888.8mV    1.234V     41.35mV
18.18ns   628.1mV    1.119V     9.016mV
22.22ns   80.12mV    813.2mV    4.118mV
34.34ns   4.868mV    29.36mV    2.434mV
200ns     2.934mV    4.52mV     2.083mV
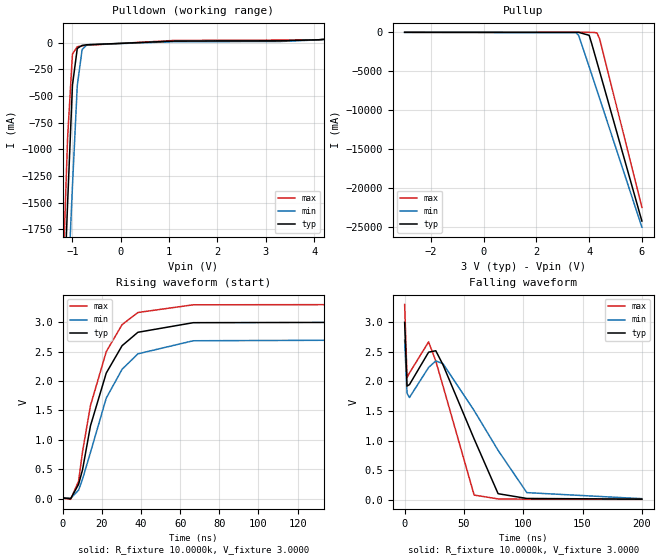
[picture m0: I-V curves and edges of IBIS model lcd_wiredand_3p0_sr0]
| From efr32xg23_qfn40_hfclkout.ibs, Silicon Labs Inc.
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|   Model lcd_wiredand_3p0_sr0
[Model]  lcd_wiredand_3p0_sr0
Model_type Output
Polarity   Inverting
Enable   Active-Low
C_comp   1.6300pF   1.4000pF   2.7000pF
[Temperature Range]   25.0000   0.1250k   -40.0000
[Pullup Reference]   3.0000V   2.7000V   3.3000V
[Pulldown Reference]   0.0V   0.0V   0.0V
[POWER Clamp Reference]   3.0000V   2.7000V   3.3000V
[GND Clamp Reference]   0.0V   0.0V   0.0V
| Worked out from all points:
|   slope of the pulldown table from 0 to 0.45 V, typ, clamps not added: 50.8 ohm
|   rising waveform, R_fixture 10.0000k, V_fixture 3.0000: 20-80 % time 15.6ns typ, 17.2ns min, 14.7ns max; typ from 0.013 V to 3 V
|   falling waveform, R_fixture 10.0000k, V_fixture 3.0000: 20-80 % time 37.1ns typ, 49.3ns min, 28.2ns max; typ from 3 V to 0.013 V
[Pulldown]
|Voltage   I(typ)   I(min)   I(max)
-3V       -24.29A    -21.98A    -26.6A
-1.2V     -2.696A    -3.401A    -2.229A
-1.1V     -1.504A    -2.372A    -891.2mA
-1V       -398.3mA   -1.347A    -105.5mA
-900mV    -52.43mA   -401.6mA   -36.73mA
-800mV    -23.94mA   -62.62mA   -28.56mA
-700mV    -18.26mA   -17.6mA    -22.48mA
1.1V      16.3mA     10.6mA     22.34mA
3.3V      18.98mA    12.75mA    25.98mA
4.1V      28.81mA    28.09mA    28.94mA
4.9V      58.91mA    54.8mA     59.74mA
6V        113.8mA    103.8mA    120mA
[Pullup]
|Voltage   I(typ)   I(min)   I(max)
-3V       338.2nA    9.289uA    587.2nA
3.5V      -430.7uA   -50.4mA    -8.469nA
3.6V      -1.559mA   -390.7mA   -692.6nA
4V        -385.8mA   -4.417A    -4.219mA
4.1V      -1.495A    -5.446A    -8.403mA
4.2V      -2.686A    -6.476A    -14.95mA
4.3V      -3.882A    -7.507A    -84.19mA
4.4V      -5.077A    -8.538A    -881.8mA
4.5V      -6.274A    -9.569A    -2.22A
4.7V      -8.669A    -11.63A    -4.917A
4.8V      -9.867A    -12.66A    -6.266A
6V        -24.27A    -25.05A    -22.51A
[Ramp]
| variable   typ   min   max
dV/dt_r  -0.1737m/32.2650p   -0.1944m/48.2248p   -0.1403m/15.1190p
dV/dt_f  1.7920/65.5066n   1.6071/85.5866n   1.9738/48.0998n
R_load = 10.0000k
[Rising Waveform]
R_fixture= 10.0000k
V_fixture= 3.0000
V_fixture_min= 2.7000
V_fixture_max= 3.3000
|time   V(typ)   V(min)   V(max)
0s        12.55mV    17.32mV    10.21mV
4.04ns    1.632mV    6.94mV     -10.16mV
8.081ns   245.3mV    146.5mV    299.1mV
10.1ns    493.3mV    334.8mV    801mV
14.14ns   1.238V     785.8mV    1.582V
22.22ns   2.136V     1.71V      2.499V
30.3ns    2.6V       2.199V     2.958V
38.38ns   2.828V     2.462V     3.164V
66.67ns   2.991V     2.684V     3.295V
200ns     3V         2.7V       3.3V
[Falling Waveform]
R_fixture= 10.0000k
V_fixture= 3.0000
V_fixture_min= 2.7000
V_fixture_max= 3.3000
|time   V(typ)   V(min)   V(max)
0s        3V         2.7V       3.3V
2.02ns    1.923V     1.801V     2.066V
4.04ns    1.947V     1.729V     2.143V
20.2ns    2.495V     2.237V     2.669V
26.26ns   2.519V     2.347V     2.344V
32.32ns   2.282V     2.3V       1.925V
58.59ns   1.03V      1.509V     82.13mV
78.79ns   105.4mV    836.8mV    17.39mV
103ns     24.96mV    123.4mV    12.7mV
200ns     13.26mV    21.4mV     10.3mV
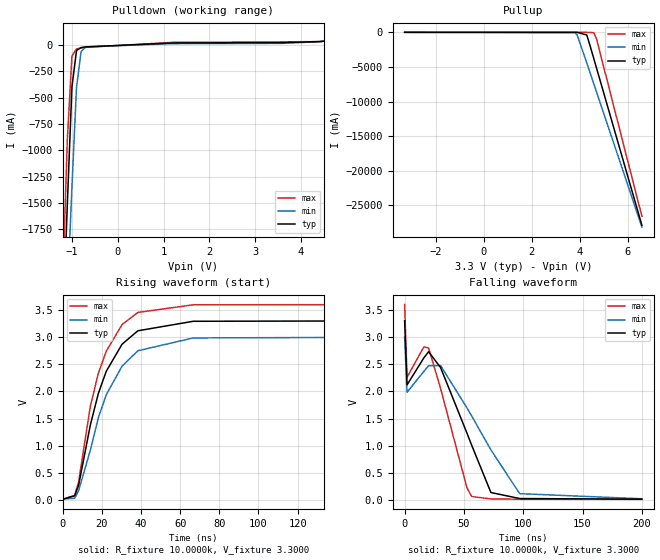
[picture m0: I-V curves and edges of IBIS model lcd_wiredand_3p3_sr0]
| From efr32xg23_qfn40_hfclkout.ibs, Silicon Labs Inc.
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|   Model lcd_wiredand_3p3_sr0
[Model]  lcd_wiredand_3p3_sr0
Model_type Output
Polarity   Inverting
Enable   Active-Low
C_comp   1.6300pF   1.4000pF   2.7000pF
[Temperature Range]   25.0000   0.1250k   -40.0000
[Pullup Reference]   3.3000V   3.0000V   3.6000V
[Pulldown Reference]   0.0V   0.0V   0.0V
[POWER Clamp Reference]   3.3000V   3.0000V   3.6000V
[GND Clamp Reference]   0.0V   0.0V   0.0V
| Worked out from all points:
|   slope of the pulldown table from 0 to 0.495 V, typ, clamps not added: 48.7 ohm
|   rising waveform, R_fixture 10.0000k, V_fixture 3.3000: 20-80 % time 15.5ns typ, 16.8ns min, 14.6ns max; typ from 0.013 V to 3.3 V
|   falling waveform, R_fixture 10.0000k, V_fixture 3.3000: 20-80 % time 36ns typ, 47.5ns min, 45.1ns max; typ from 3.3 V to 0.014 V
[Pulldown]
|Voltage   I(typ)   I(min)   I(max)
-3.3V     -27.9A     -25.09A    -30.67A
-1.2V     -2.696A    -3.401A    -2.23A
-1.1V     -1.505A    -2.373A    -891.3mA
-1V       -398.6mA   -1.347A    -105.6mA
-900mV    -52.92mA   -402.1mA   -36.92mA
-800mV    -24.42mA   -63.24mA   -28.77mA
-700mV    -18.71mA   -18.18mA   -22.69mA
1.2V      18.63mA    12.53mA    24.83mA
3.6V      21.79mA    15.2mA     28.99mA
4.4V      31.72mA    30.8mA     31.97mA
5.3V      66.75mA    62.11mA    67.95mA
6.6V      135.1mA    124.6mA    142.2mA
[Pullup]
|Voltage   I(typ)   I(min)   I(max)
-3.3V     752.9nA    36.11uA    1.107uA
3.8V      -431uA     -50.4mA    -8.644nA
3.9V      -1.56mA    -390.8mA   -699.1nA
4.3V      -385.8mA   -4.417A    -4.22mA
4.4V      -1.495A    -5.446A    -8.405mA
4.5V      -2.686A    -6.476A    -14.95mA
4.6V      -3.88A     -7.507A    -84.19mA
4.7V      -5.077A    -8.538A    -881.8mA
4.8V      -6.274A    -9.569A    -2.22A
5V        -8.669A    -11.63A    -4.913A
5.1V      -9.868A    -12.66A    -6.266A
6.6V      -27.87A    -28.14A    -26.57A
[Ramp]
| variable   typ   min   max
dV/dt_r  -0.1772m/26.8385p   -0.1984m/41.9983p   -0.1411m/13.9675p
dV/dt_f  1.9717/60.9712n   1.7871/79.0113n   2.1533/45.0826n
R_load = 10.0000k
[Rising Waveform]
R_fixture= 10.0000k
V_fixture= 3.3000
V_fixture_min= 3.0000
V_fixture_max= 3.6000
|time   V(typ)   V(min)   V(max)
0s        13.3mV     17.95mV    11.02mV
6.061ns   75.84mV    29.76mV    83.44mV
8.081ns   269.3mV    169mV      331.6mV
14.14ns   1.389V     923.3mV    1.74V
18.18ns   1.962V     1.516V     2.331V
22.22ns   2.37V      1.938V     2.74V
30.3ns    2.869V     2.465V     3.231V
38.38ns   3.116V     2.748V     3.454V
66.67ns   3.291V     2.984V     3.594V
200ns     3.3V       3V         3.6V
[Falling Waveform]
R_fixture= 10.0000k
V_fixture= 3.3000
V_fixture_min= 3.0000
V_fixture_max= 3.6000
|time   V(typ)   V(min)   V(max)
0s        3.3V       3V         3.6V
2.02ns    2.119V     1.983V     2.259V
16.16ns   2.616V     2.367V     2.818V
20.2ns    2.73V      2.472V     2.8V
30.3ns    2.438V     2.475V     2.053V
52.53ns   1.231V     1.696V     223.6mV
56.57ns   1.004V     1.544V     62.36mV
72.73ns   136.5mV    921.6mV    19mV
96.97ns   25.77mV    115.8mV    13.46mV
200ns     13.9mV     21.46mV    11.07mV
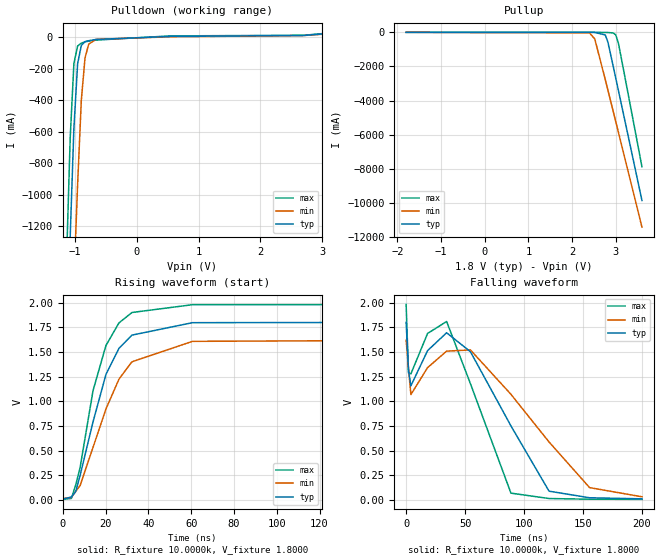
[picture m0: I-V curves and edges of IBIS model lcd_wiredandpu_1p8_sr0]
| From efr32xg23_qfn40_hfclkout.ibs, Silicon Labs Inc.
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|   Model lcd_wiredandpu_1p8_sr0
[Model]  lcd_wiredandpu_1p8_sr0
Model_type Output
Polarity   Inverting
Enable   Active-Low
C_comp   1.6300pF   1.4000pF   2.7000pF
[Temperature Range]   25.0000   0.1250k   -40.0000
[Pullup Reference]   1.8000V   1.6200V   1.9800V
[Pulldown Reference]   0.0V   0.0V   0.0V
[POWER Clamp Reference]   1.8000V   1.6200V   1.9800V
[GND Clamp Reference]   0.0V   0.0V   0.0V
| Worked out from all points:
|   slope of the pulldown table from 0 to 0.27 V, typ, clamps not added: 73.7 ohm
|   slope of the pullup table from 0 to 0.27 V, typ, clamps not added: 41.1 kohm
|   rising waveform, R_fixture 10.0000k, V_fixture 1.8000: 20-80 % time 14ns typ, 17.2ns min, 12ns max; typ from 0.011 V to 1.8 V
|   falling waveform, R_fixture 10.0000k, V_fixture 1.8000: 20-80 % time 47.9ns typ, 64.3ns min, 34.3ns max; typ from 1.8 V to 0.013 V
[Pulldown]
|Voltage   I(typ)   I(min)   I(max)
-1.8V     -9.882A    -9.584A    -10.33A
-1.14V    -1.981A    -2.781A    -1.427A
-1.08V    -1.267A    -2.165A    -640.1mA
-1.02V    -576.7mA   -1.55A     -166.6mA
-960mV    -168.5mA   -936.7mA   -54.94mA
-900mV    -51.19mA   -400.2mA   -36.82mA
-840mV    -27.26mA   -130.9mA   -28.21mA
-780mV    -21.22mA   -42.93mA   -24.16mA
-660mV    -13.38mA   -12.47mA   -17.5mA
540mV     5.932mA    3.464mA    9.194mA
2.7V      11.8mA     11.46mA    13.06mA
3.6V      40.83mA    35.69mA    44.97mA
[Pullup]
|Voltage   I(typ)   I(min)   I(max)
-1.8V     42.99uA    36.68uA    50.46uA
2.4V      -1.602mA   -34.07mA   -114.4uA
2.52V     -4.349mA   -392mA     -710.8uA
2.76V     -155.8mA   -2.773A    -7.492mA
2.82V     -568mA     -3.389A    -10.53mA
2.94V     -1.973A    -4.623A    -35.81mA
3V        -2.688A    -5.241A    -149.8mA
3.06V     -3.404A    -5.859A    -630.5mA
3.12V     -4.12A     -6.477A    -1.419A
3.24V     -5.555A    -7.713A    -3.03A
3.3V      -6.273A    -8.332A    -3.837A
3.6V      -9.867A    -11.43A    -7.886A
[Ramp]
| variable   typ   min   max
dV/dt_r  0.2111/14.0828n   0.1681/16.1981n   0.2624/12.5150n
dV/dt_f  1.0722/0.1037u   0.9516/0.1346u   1.1832/75.3997n
R_load = 10.0000k
[Rising Waveform]
R_fixture= 10.0000k
V_fixture= 1.8000
V_fixture_min= 1.6200
V_fixture_max= 1.9800
|time   V(typ)   V(min)   V(max)
0s        10.84mV    16.66mV    7.706mV
4.04ns    30.69mV    27.19mV    16.79mV
6.061ns   87.34mV    89.58mV    154.6mV
8.081ns   248.5mV    146.1mV    327.8mV
14.14ns   792.5mV    534.2mV    1.109V
20.2ns    1.274V     924mV      1.566V
26.26ns   1.536V     1.224V     1.794V
32.32ns   1.67V      1.4V       1.899V
60.61ns   1.796V     1.607V     1.978V
200ns     1.8V       1.62V      1.98V
[Falling Waveform]
R_fixture= 10.0000k
V_fixture= 1.8000
V_fixture_min= 1.6200
V_fixture_max= 1.9800
|time   V(typ)   V(min)   V(max)
0s        1.8V       1.62V      1.98V
2.02ns    1.313V     1.331V     1.286V
4.04ns    1.157V     1.068V     1.278V
18.18ns   1.513V     1.341V     1.687V
34.34ns   1.694V     1.508V     1.808V
54.55ns   1.502V     1.52V      1.178V
88.89ns   751.1mV    1.071V     70.8mV
121.2ns   90.65mV    588.5mV    16.2mV
155.6ns   23.87mV    126.5mV    9.154mV
200ns     12.97mV    33.88mV    8.027mV
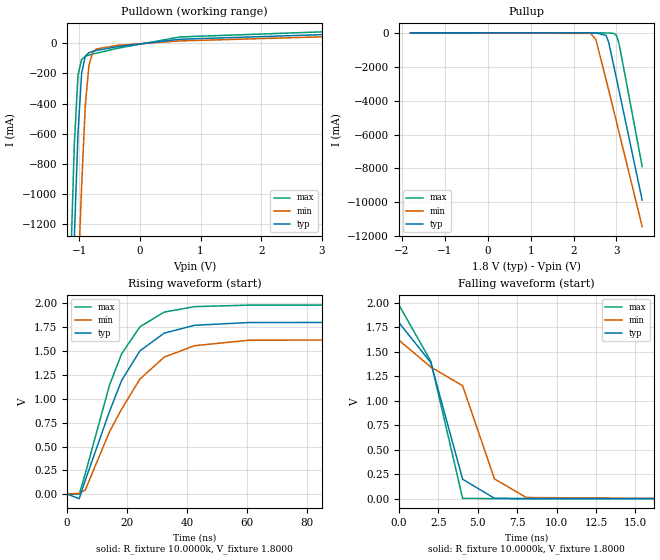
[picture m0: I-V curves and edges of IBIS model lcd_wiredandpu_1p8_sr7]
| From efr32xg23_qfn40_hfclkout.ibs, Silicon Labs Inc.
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|   Model lcd_wiredandpu_1p8_sr7
[Model]  lcd_wiredandpu_1p8_sr7
Model_type Output
Polarity   Inverting
Enable   Active-Low
C_comp   1.6300pF   1.4000pF   2.7000pF
[Temperature Range]   25.0000   0.1250k   -40.0000
[Pullup Reference]   1.8000V   1.6200V   1.9800V
[Pulldown Reference]   0.0V   0.0V   0.0V
[POWER Clamp Reference]   1.8000V   1.6200V   1.9800V
[GND Clamp Reference]   0.0V   0.0V   0.0V
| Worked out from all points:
|   slope of the pulldown table from 0 to 0.27 V, typ, clamps not added: 19.4 ohm
|   slope of the pullup table from 0 to 0.27 V, typ, clamps not added: 41.1 kohm
|   rising waveform, R_fixture 10.0000k, V_fixture 1.8000: 20-80 % time 14.4ns typ, 17.3ns min, 12ns max; typ from 0.003 V to 1.8 V
|   falling waveform, R_fixture 10.0000k, V_fixture 1.8000: 20-80 % time 1.99ns typ, 3.26ns min, 2.08ns max; typ from 1.8 V to 0.003 V
[Pulldown]
|Voltage   I(typ)   I(min)   I(max)
-1.8V     -9.89A     -9.587A    -10.35A
-1.14V    -1.996A    -2.789A    -1.448A
-1.08V    -1.283A    -2.173A    -665.1mA
-1.02V    -596.5mA   -1.559A    -212.1mA
-960mV    -199.8mA   -946.1mA   -107.3mA
-900mV    -87.05mA   -413.4mA   -88.64mA
-840mV    -62.82mA   -148.8mA   -78.59mA
-780mV    -55.48mA   -62.77mA   -72.78mA
-720mV    -48.51mA   -39.03mA   -67.07mA
-360mV    -23.12mA   -14.48mA   -33.62mA
660mV     25.51mA    14.47mA    40.77mA
3.6V      63.81mA    48.33mA    83.02mA
[Pullup]
|Voltage   I(typ)   I(min)   I(max)
-1.8V     42.99uA    36.68uA    50.46uA
2.4V      -1.602mA   -34.07mA   -114.4uA
2.52V     -4.349mA   -392mA     -710.8uA
2.76V     -155.8mA   -2.773A    -7.492mA
2.82V     -568mA     -3.389A    -10.53mA
2.94V     -1.973A    -4.623A    -35.81mA
3V        -2.688A    -5.241A    -149.8mA
3.06V     -3.404A    -5.859A    -630.5mA
3.12V     -4.12A     -6.477A    -1.419A
3.24V     -5.555A    -7.713A    -3.03A
3.3V      -6.273A    -8.332A    -3.837A
3.6V      -9.867A    -11.43A    -7.886A
[Ramp]
| variable   typ   min   max
dV/dt_r  0.2110/13.8988n   0.1681/15.8891n   0.2623/12.4613n
dV/dt_f  1.0782/1.9869n   0.9693/3.2596n   1.1867/2.0835n
R_load = 10.0000k
[Rising Waveform]
R_fixture= 10.0000k
V_fixture= 1.8000
V_fixture_min= 1.6200
V_fixture_max= 1.9800
|time   V(typ)   V(min)   V(max)
0s        2.931mV    4.511mV    2.082mV
4.04ns    -45.36mV   10.44mV    1.722mV
6.061ns   147.6mV    45.27mV    215.8mV
14.14ns   867.8mV    656mV      1.144V
18.18ns   1.192V     891.9mV    1.47V
24.24ns   1.499V     1.205V     1.751V
32.32ns   1.685V     1.434V     1.905V
42.42ns   1.767V     1.554V     1.962V
60.61ns   1.796V     1.611V     1.978V
200ns     1.8V       1.62V      1.98V
[Falling Waveform]
R_fixture= 10.0000k
V_fixture= 1.8000
V_fixture_min= 1.6200
V_fixture_max= 1.9800
|time   V(typ)   V(min)   V(max)
0s        1.8V       1.62V      1.98V
2.02ns    1.392V     1.346V     1.406V
4.04ns    200.6mV    1.155V     5.812mV
6.061ns   6.359mV    203.3mV    2.452mV
8.081ns   3.583mV    14.4mV     2.181mV
16.16ns   2.987mV    4.752mV    2.106mV
200ns     2.933mV    4.515mV    2.083mV
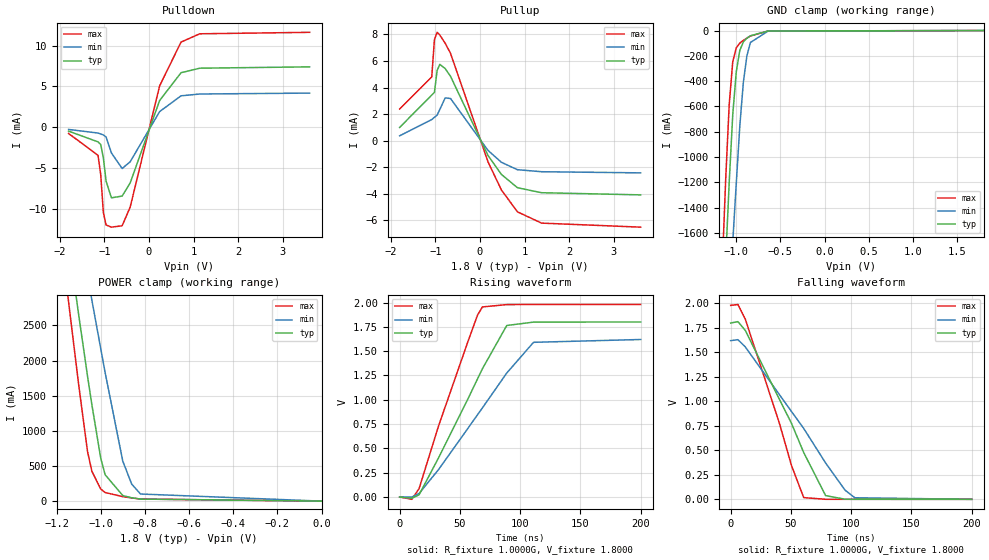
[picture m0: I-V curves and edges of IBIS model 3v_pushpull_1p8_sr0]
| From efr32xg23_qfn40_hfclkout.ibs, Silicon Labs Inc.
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|   Model 3v_pushpull_1p8_sr0
[Model]  3v_pushpull_1p8_sr0
Model_type 3-state
Polarity   Non-Inverting
Enable   Active-High
C_comp   1.6300pF   1.4000pF   2.7000pF
[Temperature Range]   25.0000   0.1250k   -40.0000
[Pullup Reference]   1.8000V   1.6200V   1.9800V
[Pulldown Reference]   0.0V   0.0V   0.0V
[POWER Clamp Reference]   1.8000V   1.6200V   1.9800V
[GND Clamp Reference]   0.0V   0.0V   0.0V
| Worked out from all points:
|   slope of the pulldown table from 0 to 0.27 V, typ, clamps not added: 74.9 ohm
|   slope of the pullup table from 0 to 0.27 V, typ, clamps not added: 170 ohm
|   GND clamp passes 1 mA (typ) near -0.52 V on its own axis
|   POWER clamp passes 1 mA (typ) near -0.53 V on its own axis
|   rising waveform, R_fixture 1.0000G, V_fixture 1.8000: 20-80 % time 42.8ns typ, 55.6ns min, 32ns max; typ from 0 V to 1.8 V
|   falling waveform, R_fixture 1.0000G, V_fixture 1.8000: 20-80 % time 40.7ns typ, 53.5ns min, 30.1ns max; typ from 1.8 V to 0 V
[Pulldown]
|Voltage   I(typ)   I(min)   I(max)
-1.8V     -463uA     -259.7uA   -753.3uA
-1.14V    -1.783mA   -700.7uA   -3.429mA
-1.08V    -2.102mA   -812.6uA   -5.777mA
-1.02V    -3.758mA   -932.8uA   -10.46mA
-960mV    -6.584mA   -1.183mA   -11.95mA
-840mV    -8.628mA   -3.138mA   -12.22mA
-600mV    -8.415mA   -5.041mA   -12.05mA
-420mV    -6.808mA   -4.216mA   -9.767mA
240mV     3.286mA    1.928mA    5.078mA
720mV     6.687mA    3.858mA    10.44mA
1.14V     7.239mA    4.08mA     11.45mA
3.6V      7.403mA    4.19mA     11.63mA
[Pullup]
|Voltage   I(typ)   I(min)   I(max)
-1.8V     1.001mA    370.1uA    2.388mA
-1.08V    3.44mA     1.596mA    4.807mA
-1.02V    3.643mA    1.767mA    7.606mA
-960mV    5.287mA    1.926mA    8.16mA
-900mV    5.749mA    2.352mA    7.959mA
-780mV    5.434mA    3.224mA    7.342mA
-660mV    4.853mA    3.181mA    6.581mA
180mV     -1.11mA    -726.7uA   -1.588mA
480mV     -2.532mA   -1.62mA    -3.702mA
840mV     -3.535mA   -2.181mA   -5.351mA
1.38V     -3.911mA   -2.331mA   -6.199mA
3.6V      -4.074mA   -2.417mA   -6.503mA
[GND_clamp]
|Voltage   I(typ)   I(min)   I(max)
-1.8V     -14.24A    -14.11A    -14.46A
-1.16V    -2.476A    -3.328A    -1.893A
-1.12V    -1.809A    -2.723A    -1.176A
-1.08V    -1.199A    -2.174A    -584.5mA
-1.04V    -665.3mA   -1.671A    -246.2mA
-1V       -325.1mA   -1.206A    -136.4mA
-960mV    -156.4mA   -753.1mA   -99.65mA
-920mV    -90.21mA   -408.8mA   -78.05mA
-880mV    -60.4mA    -199.9mA   -59.73mA
-840mV    -41.37mA   -94.67mA   -43.12mA
-640mV    -3.804mA   -4.268mA   -4.1mA
1.8V      625.9pA    920.5nA    498.3pA
[POWER_clamp]
|Voltage   I(typ)   I(min)   I(max)
-1.8V     20.85A     19.71A     22.07A
-1.16V    4.023A     5.096A     3.217A
-1.14V    3.56A      4.702A     2.691A
-1.1V     2.657A     3.938A     1.662A
-1.06V    1.784A     3.203A     710.9mA
-1.04V    1.371A     2.858A     424.9mA
-1V       612.3mA    2.171A     172.3mA
-980mV    375.2mA    1.828A     122.5mA
-900mV    79.36mA    567.5mA    63.7mA
-860mV    47.61mA    243.6mA    45.04mA
-820mV    29.31mA    101.4mA    29.65mA
0V        625.9pA    9.472nA    580.1pA
[Ramp]
| variable   typ   min   max
dV/dt_r  1.0626/47.3586n   0.9457/62.5654n   1.1751/34.8344n
dV/dt_f  1.0728/47.0359n   0.9589/63.5922n   1.1832/33.5872n
R_load = 10.0000k
[Rising Waveform]
R_fixture= 1.0000G
V_fixture= 1.8000
V_fixture_min= 1.6200
V_fixture_max= 1.9800
|time   V(typ)   V(min)   V(max)
0s        22.59uV    80.14uV    8.254uV
10.1ns    -12.67mV   -811.3uV   -24mV
16.16ns   22.51mV    36.44mV    86.58mV
32.32ns   403.3mV    282.3mV    731.6mV
56.57ns   1.006V     704.7mV    1.595V
64.65ns   1.215V     846.2mV    1.871V
68.69ns   1.319V     916.3mV    1.955V
88.89ns   1.764V     1.275V     1.979V
111.1ns   1.799V     1.591V     1.98V
200ns     1.8V       1.62V      1.98V
[Falling Waveform]
R_fixture= 1.0000G
V_fixture= 1.8000
V_fixture_min= 1.6200
V_fixture_max= 1.9800
|time   V(typ)   V(min)   V(max)
0s        1.8V       1.62V      1.98V
6.061ns   1.814V     1.63V      1.989V
12.12ns   1.725V     1.556V     1.84V
40.4ns    1.022V     1.07V      778.1mV
50.51ns   774.8mV    896.1mV    343.7mV
60.61ns   477.5mV    723.8mV    17.65mV
78.79ns   37.95mV    370.8mV    433.7uV
94.95ns   1.08mV     93.32mV    211.3uV
103ns     638.1uV    16.12mV    159uV
200ns     22.92uV    83.87uV    8.36uV
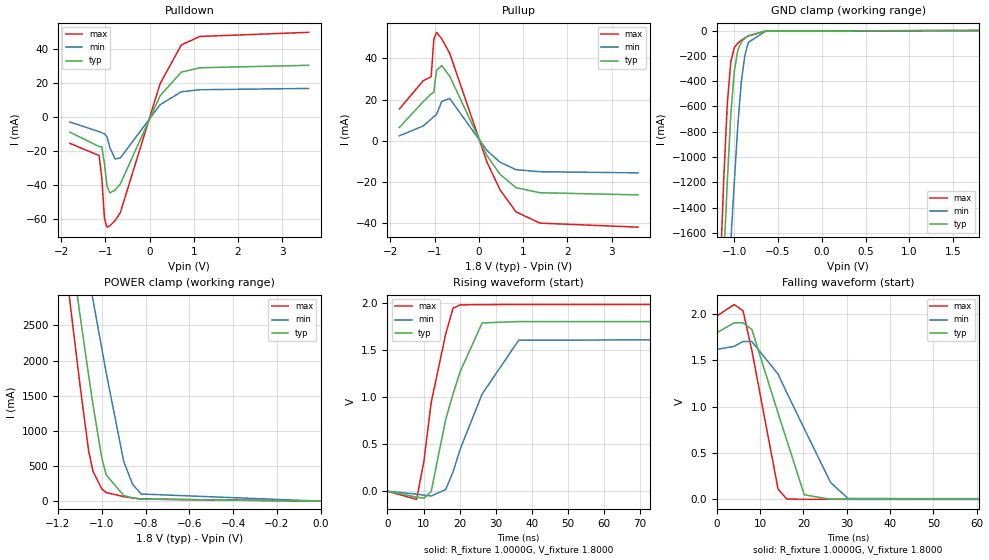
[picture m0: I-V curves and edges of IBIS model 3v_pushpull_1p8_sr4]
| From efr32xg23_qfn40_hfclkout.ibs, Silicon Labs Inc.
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|   Model 3v_pushpull_1p8_sr4
[Model]  3v_pushpull_1p8_sr4
Model_type 3-state
Polarity   Non-Inverting
Enable   Active-High
C_comp   1.6300pF   1.4000pF   2.7000pF
[Temperature Range]   25.0000   0.1250k   -40.0000
[Pullup Reference]   1.8000V   1.6200V   1.9800V
[Pulldown Reference]   0.0V   0.0V   0.0V
[POWER Clamp Reference]   1.8000V   1.6200V   1.9800V
[GND Clamp Reference]   0.0V   0.0V   0.0V
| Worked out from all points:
|   slope of the pulldown table from 0 to 0.27 V, typ, clamps not added: 19.5 ohm
|   slope of the pullup table from 0 to 0.27 V, typ, clamps not added: 26.3 ohm
|   GND clamp passes 1 mA (typ) near -0.52 V on its own axis
|   POWER clamp passes 1 mA (typ) near -0.53 V on its own axis
|   rising waveform, R_fixture 1.0000G, V_fixture 1.8000: 20-80 % time 7.44ns typ, 10.8ns min, 5.31ns max; typ from 0 V to 1.8 V
|   falling waveform, R_fixture 1.0000G, V_fixture 1.8000: 20-80 % time 6.79ns typ, 9.97ns min, 4.77ns max; typ from 1.8 V to 0 V
[Pulldown]
|Voltage   I(typ)   I(min)   I(max)
-1.8V     -8.927mA   -2.968mA   -15.46mA
-1.14V    -17.33mA   -8.573mA   -22.65mA
-1.08V    -17.39mA   -9.249mA   -35.66mA
-1.02V    -27.55mA   -9.89mA    -59.6mA
-960mV    -40.66mA   -11.71mA   -64.78mA
-900mV    -44.59mA   -17.79mA   -64.09mA
-780mV    -42.99mA   -24.61mA   -60.92mA
-660mV    -39.29mA   -24.02mA   -56.16mA
240mV     12.6mA     7.302mA    19.7mA
720mV     26.45mA    14.92mA    42.48mA
1.14V     29.02mA    16.1mA     47.45mA
3.6V      30.48mA    16.86mA    49.88mA
[Pullup]
|Voltage   I(typ)   I(min)   I(max)
-1.8V     6.468mA    2.392mA    15.43mA
-1.26V    18.97mA    7.189mA    29.18mA
-1.08V    22.76mA    10.57mA    31.06mA
-1.02V    23.54mA    11.7mA     49.2mA
-960mV    34.21mA    12.71mA    52.72mA
-840mV    36.58mA    19.15mA    49.55mA
-660mV    31.36mA    20.55mA    42.52mA
180mV     -7.173mA   -4.696mA   -10.26mA
480mV     -16.36mA   -10.47mA   -23.92mA
840mV     -22.84mA   -14.09mA   -34.58mA
1.38V     -25.27mA   -15.06mA   -40.06mA
3.6V      -26.33mA   -15.62mA   -42.02mA
[GND_clamp]
|Voltage   I(typ)   I(min)   I(max)
-1.8V     -14.24A    -14.11A    -14.46A
-1.16V    -2.476A    -3.328A    -1.893A
-1.12V    -1.809A    -2.723A    -1.176A
-1.08V    -1.199A    -2.174A    -584.5mA
-1.04V    -665.3mA   -1.671A    -246.2mA
-1V       -325.1mA   -1.206A    -136.4mA
-960mV    -156.4mA   -753.1mA   -99.65mA
-920mV    -90.21mA   -408.8mA   -78.05mA
-880mV    -60.4mA    -199.9mA   -59.73mA
-840mV    -41.37mA   -94.67mA   -43.12mA
-640mV    -3.804mA   -4.268mA   -4.1mA
1.8V      625.9pA    920.5nA    498.3pA
[POWER_clamp]
|Voltage   I(typ)   I(min)   I(max)
-1.8V     20.85A     19.71A     22.07A
-1.16V    4.023A     5.096A     3.217A
-1.14V    3.56A      4.702A     2.691A
-1.1V     2.657A     3.938A     1.662A
-1.06V    1.784A     3.203A     710.9mA
-1.04V    1.371A     2.858A     424.9mA
-1V       612.3mA    2.171A     172.3mA
-980mV    375.2mA    1.828A     122.5mA
-900mV    79.36mA    567.5mA    63.7mA
-860mV    47.61mA    243.6mA    45.04mA
-820mV    29.31mA    101.4mA    29.65mA
0V        625.9pA    9.472nA    580.1pA
[Ramp]
| variable   typ   min   max
dV/dt_r  1.0775/7.9515n   0.9686/11.9000n   1.1861/5.5557n
dV/dt_f  1.0782/7.1944n   0.9693/10.8648n   1.1867/4.9719n
R_load = 10.0000k
[Rising Waveform]
R_fixture= 1.0000G
V_fixture= 1.8000
V_fixture_min= 1.6200
V_fixture_max= 1.9800
|time   V(typ)   V(min)   V(max)
0s        2.01uV     4.874uV    944nV
8.081ns   -62.01mV   -30.22mV   -85.63mV
10.1ns    -73.54mV   -41.73mV   314.7mV
12.12ns   -3.934mV   -50.66mV   939.6mV
16.16ns   763.1mV    19.35mV    1.67V
18.18ns   1.032V     206.2mV    1.941V
20.2ns    1.273V     450.5mV    1.976V
26.26ns   1.785V     1.032V     1.979V
36.36ns   1.799V     1.601V     1.98V
200ns     1.8V       1.62V      1.98V
[Falling Waveform]
R_fixture= 1.0000G
V_fixture= 1.8000
V_fixture_min= 1.6200
V_fixture_max= 1.9800
|time   V(typ)   V(min)   V(max)
0s        1.8V       1.62V      1.98V
4.04ns    1.908V     1.653V     2.105V
6.061ns   1.908V     1.706V     2.036V
8.081ns   1.837V     1.705V     1.613V
14.14ns   931.7mV    1.353V     112mV
16.16ns   637.7mV    1.152V     2.508mV
20.2ns    48.76mV    762.6mV    522.2uV
26.26ns   871.8uV    183.1mV    212.3uV
30.3ns    459.1uV    8.665mV    125uV
200ns     1.679uV    4.876uV    1.003uV
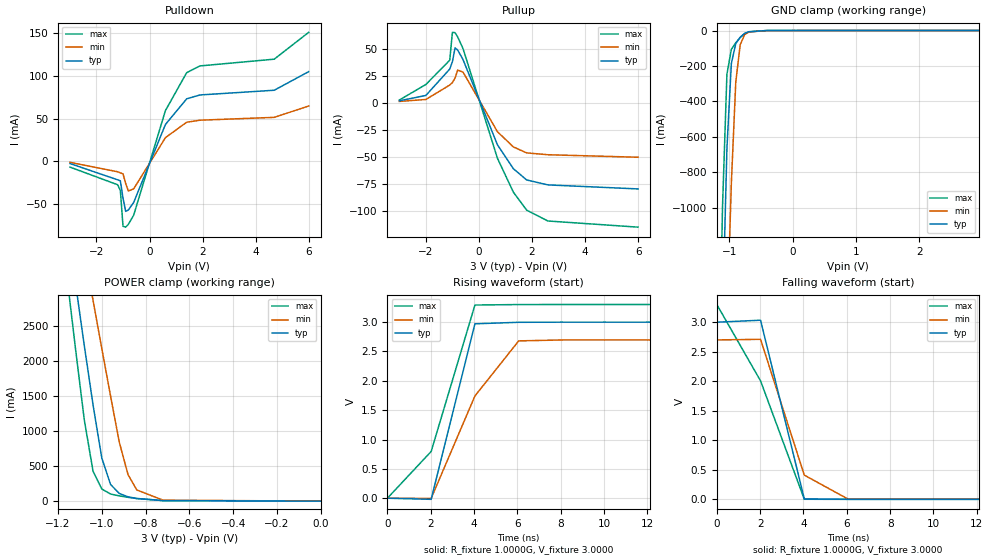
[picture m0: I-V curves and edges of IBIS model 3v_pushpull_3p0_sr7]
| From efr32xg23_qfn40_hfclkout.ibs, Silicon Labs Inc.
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|   Model 3v_pushpull_3p0_sr7
[Model]  3v_pushpull_3p0_sr7
Model_type 3-state
Polarity   Non-Inverting
Enable   Active-High
C_comp   1.6300pF   1.4000pF   2.7000pF
[Temperature Range]   25.0000   0.1250k   -40.0000
[Pullup Reference]   3.0000V   2.7000V   3.3000V
[Pulldown Reference]   0.0V   0.0V   0.0V
[POWER Clamp Reference]   3.0000V   2.7000V   3.3000V
[GND Clamp Reference]   0.0V   0.0V   0.0V
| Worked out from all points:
|   slope of the pulldown table from 0 to 0.45 V, typ, clamps not added: 13.2 ohm
|   slope of the pullup table from 0 to 0.45 V, typ, clamps not added: 16.9 ohm
|   GND clamp passes 1 mA (typ) near -0.52 V on its own axis
|   POWER clamp passes 1 mA (typ) near -0.53 V on its own axis
|   rising waveform, R_fixture 1.0000G, V_fixture 3.0000: 20-80 % time 1.22ns typ, 2.29ns min, 1.84ns max; typ from 0 V to 3 V
|   falling waveform, R_fixture 1.0000G, V_fixture 3.0000: 20-80 % time 1.2ns typ, 1.42ns min, 2.35ns max; typ from 3 V to 0 V
[Pulldown]
|Voltage   I(typ)   I(min)   I(max)
-3V       -2.683mA   -1.298mA   -6.873mA
-1.2V     -21.82mA   -12.36mA   -27.6mA
-1.1V     -22.98mA   -13.65mA   -34.34mA
-1V       -43.29mA   -14.82mA   -76.27mA
-900mV    -58.8mA    -26.03mA   -77.31mA
-800mV    -57.22mA   -34.88mA   -74.02mA
-600mV    -48.47mA   -32.44mA   -63.42mA
600mV     43.14mA    27.68mA    59.46mA
1.4V      73.21mA    45.76mA    103.9mA
1.9V      77.74mA    48.13mA    111.8mA
4.7V      83.26mA    51.46mA    119.7mA
6V        105.1mA    64.77mA    151.2mA
[Pullup]
|Voltage   I(typ)   I(min)   I(max)
-3V       1.824mA    1.228mA    2.526mA
-2V       6.772mA    3.05mA     16.9mA
-1.1V     31.18mA    16.39mA    39.36mA
-1V       37.96mA    18.68mA    65.17mA
-900mV    50.75mA    22.86mA    64.88mA
-800mV    48.76mA    30.25mA    60.85mA
-600mV    39.95mA    28.38mA    50.21mA
700mV     -38.98mA   -26.85mA   -51.49mA
1.3V      -61.08mA   -40.88mA   -82.76mA
1.8V      -71.42mA   -46.38mA   -99.36mA
2.6V      -76mA      -48.1mA    -109.4mA
6V        -79.73mA   -50.42mA   -115.1mA
[GND_clamp]
|Voltage   I(typ)   I(min)   I(max)
-3V       -32.58A    -30.59A    -34.3A
-1.18V    -2.82A     -3.643A    -2.261A
-1.11V    -1.644A    -2.575A    -1.001A
-1.04V    -666.4mA   -1.673A    -246.5mA
-970mV    -186.7mA   -861.8mA   -106.7mA
-900mV    -73.86mA   -290.7mA   -68.98mA
-830mV    -38.01mA   -80.48mA   -39.62mA
-760mV    -15.97mA   -23.02mA   -17.36mA
-690mV    -6.612mA   -7.853mA   -7.292mA
-410mV    -117.4uA   -298.1uA   -56.99uA
2.95V     978pA      6.282uA    846.4pA
[POWER_clamp]
|Voltage   I(typ)   I(min)   I(max)
-3V       48.87A     43.6A      53.88A
-1.16V    4.025A     5.101A     3.218A
-1.12V    3.102A     4.315A     2.168A
-1.08V    2.218A     3.569A     1.158A
-1.04V    1.372A     2.862A     425.9mA
-1V       614.1mA    2.175A     173.1mA
-960mV    237.5mA    1.499A     101.5mA
-920mV    109mA      838.4mA    74.91mA
-880mV    61.26mA    377.1mA    54.02mA
-840mV    37.84mA    159.1mA    37.05mA
-720mV    7.412mA    13.58mA    7.87mA
0V        1.019nA    10.64nA    1.026nA
[Ramp]
| variable   typ   min   max
dV/dt_r  1.7973/1.2174n   1.6165/2.3120n   1.9777/1.8259n
dV/dt_f  1.7980/1.2013n   1.6172/1.4354n   1.9783/2.3443n
R_load = 10.0000k
[Rising Waveform]
R_fixture= 1.0000G
V_fixture= 3.0000
V_fixture_min= 2.7000
V_fixture_max= 3.3000
|time   V(typ)   V(min)   V(max)
0s        946.3nV    1.994uV    575.6nV
2.02ns    -19.17mV   -2.483mV   796.5mV
4.04ns    2.971V     1.742V     3.291V
6.061ns   2.997V     2.68V      3.299V
8.081ns   2.999V     2.696V     3.3V
200ns     3V         2.7V       3.3V
[Falling Waveform]
R_fixture= 1.0000G
V_fixture= 3.0000
V_fixture_min= 2.7000
V_fixture_max= 3.3000
|time   V(typ)   V(min)   V(max)
0s        3V         2.7V       3.3V
2.02ns    3.034V     2.71V      2.007V
4.04ns    6.386mV    409.7mV    1.26mV
6.061ns   507.8uV    4.013mV    95.34uV
200ns     986nV      1.67uV     558.7nV
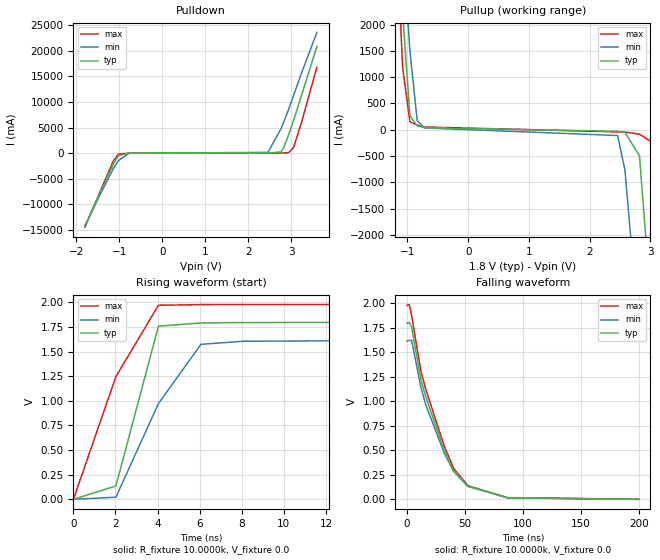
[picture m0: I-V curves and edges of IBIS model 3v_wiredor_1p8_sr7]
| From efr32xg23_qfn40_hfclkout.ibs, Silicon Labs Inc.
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|   Model 3v_wiredor_1p8_sr7
[Model]  3v_wiredor_1p8_sr7
Model_type Output
Polarity   Non-Inverting
Enable   Active-Low
C_comp   1.6300pF   1.4000pF   2.7000pF
[Temperature Range]   25.0000   0.1250k   -40.0000
[Pullup Reference]   1.8000V   1.6200V   1.9800V
[Pulldown Reference]   0.0V   0.0V   0.0V
[POWER Clamp Reference]   1.8000V   1.6200V   1.9800V
[GND Clamp Reference]   0.0V   0.0V   0.0V
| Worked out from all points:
|   slope of the pullup table from 0 to 0.27 V, typ, clamps not added: 26.3 ohm
|   rising waveform, R_fixture 10.0000k, V_fixture 0.0: 20-80 % time 1.34ns typ, 2.45ns min, 2.32ns max; typ from 0 V to 1.8 V
|   falling waveform, R_fixture 10.0000k, V_fixture 0.0: 20-80 % time 28.7ns typ, 29ns min, 29.1ns max; typ from 1.8 V to 0.001 V
[Pulldown]
|Voltage   I(typ)   I(min)   I(max)
-1.8V     -14.24A    -14.11A    -14.46A
-1.38V    -6.468A    -6.98A     -6.16A
-1.14V    -2.14A     -3.023A    -1.532A
-1.02V    -472.4mA   -1.439A    -175.3mA
-780mV    -21.13mA   -32.28mA   -22.88mA
2.46V     4.005mA    156.9mA    238.6uA
2.76V     235.8mA    4.702A     17.81mA
2.82V     958.6mA    5.911A     36.63mA
2.94V     3.56A      8.545A     100.8mA
3.06V     6.47A      11.36A     1.157A
3.24V     11.25A     15.63A     5.98A
3.6V      20.85A     23.6A      16.79A
[Pullup]
|Voltage   I(typ)   I(min)   I(max)
-1.8V     20.86A     19.71A     22.08A
-1.2V     4.996A     5.919A     4.326A
-1.08V    2.239A     3.576A     1.188A
-960mV    270.1mA    1.509A     153.5mA
-840mV    73.79mA    176mA      86.18mA
-720mV    40.46mA    33.96mA    52.78mA
2.46V     -30.6mA    -110.1mA   -41.67mA
2.58V     -47.09mA   -768.5mA   -43.99mA
2.82V     -498.4mA   -3.974A    -84.68mA
3V        -3.194A    -6.995A    -216.9mA
3.24V     -7.63A     -11.15A    -3.824A
3.6V      -14.27A    -16.88A    -11.03A
[Ramp]
| variable   typ   min   max
dV/dt_r  1.0775/1.3429n   0.9686/2.4539n   1.1861/2.3171n
dV/dt_f  -8.7399u/1.9119p   42.9150u/18.9434n   -7.3635u/1.0929p
R_load = 10.0000k
[Rising Waveform]
R_fixture= 10.0000k
V_fixture= 0.0
V_fixture_min= 0.0
V_fixture_max= 0.0
|time   V(typ)   V(min)   V(max)
0s        5.684uV    72.78uV    5.763uV
2.02ns    135.9mV    21.61mV    1.245V
4.04ns    1.757V     971.4mV    1.969V
6.061ns   1.79V      1.573V     1.976V
8.081ns   1.794V     1.604V     1.977V
18.18ns   1.796V     1.614V     1.977V
200ns     1.796V     1.614V     1.977V
[Falling Waveform]
R_fixture= 10.0000k
V_fixture= 0.0
V_fixture_min= 0.0
V_fixture_max= 0.0
|time   V(typ)   V(min)   V(max)
0s        1.796V     1.614V     1.977V
2.02ns    1.804V     1.62V      1.987V
4.04ns    1.758V     1.624V     1.878V
12.12ns   1.218V     1.139V     1.303V
16.16ns   1.051V     968.2mV    1.127V
32.32ns   490.9mV    468.3mV    538.6mV
40.4ns    290.5mV    283.9mV    314.6mV
52.53ns   132.6mV    133.8mV    140.6mV
86.87ns   16.27mV    18.23mV    15.99mV
200ns     964.3uV    1.295mV    783.6uV
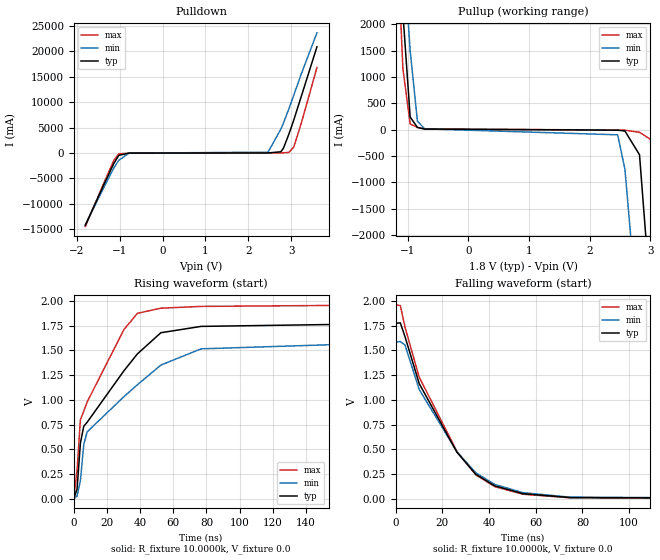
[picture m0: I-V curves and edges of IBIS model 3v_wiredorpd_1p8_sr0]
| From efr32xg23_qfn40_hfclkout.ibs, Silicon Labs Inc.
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|   Model 3v_wiredorpd_1p8_sr0
[Model]  3v_wiredorpd_1p8_sr0
Model_type Output
Polarity   Non-Inverting
Enable   Active-Low
C_comp   1.6300pF   1.4000pF   2.7000pF
[Temperature Range]   25.0000   0.1250k   -40.0000
[Pullup Reference]   1.8000V   1.6200V   1.9800V
[Pulldown Reference]   0.0V   0.0V   0.0V
[POWER Clamp Reference]   1.8000V   1.6200V   1.9800V
[GND Clamp Reference]   0.0V   0.0V   0.0V
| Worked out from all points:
|   slope of the pulldown table from 0 to 0.27 V, typ, clamps not added: 44.9 kohm
|   slope of the pullup table from 0 to 0.27 V, typ, clamps not added: 170 ohm
|   rising waveform, R_fixture 10.0000k, V_fixture 0.0: 20-80 % time 33ns typ, 41.4ns min, 23.2ns max; typ from 0 V to 1.77 V
|   falling waveform, R_fixture 10.0000k, V_fixture 0.0: 20-80 % time 23.3ns typ, 24.2ns min, 22.9ns max; typ from 1.77 V to 0.001 V
[Pulldown]
|Voltage   I(typ)   I(min)   I(max)
-1.8V     -14.24A    -14.11A    -14.46A
-1.38V    -6.468A    -6.98A     -6.16A
-1.14V    -2.14A     -3.023A    -1.532A
-1.02V    -472.4mA   -1.439A    -175.3mA
-780mV    -21.14mA   -32.29mA   -22.9mA
2.46V     4.055mA    156.9mA    301.8uA
2.76V     235.9mA    4.702A     17.88mA
2.82V     958.6mA    5.911A     36.7mA
2.94V     3.56A      8.545A     100.9mA
3.06V     6.47A      11.36A     1.157A
3.24V     11.25A     15.63A     5.98A
3.6V      20.85A     23.6A      16.79A
[Pullup]
|Voltage   I(typ)   I(min)   I(max)
-1.8V     20.85A     19.71A     22.07A
-1.2V     4.979A     5.912A     4.301A
-1.08V    2.219A     3.567A     1.162A
-960mV    241.1mA    1.498A     109mA
-840mV    42.87mA    159.9mA    44.3mA
-720mV    12.28mA    16.09mA    14.65mA
2.46V     -8.7mA     -97.07mA   -6.739mA
2.58V     -25.15mA   -755.5mA   -8.986mA
2.82V     -476.4mA   -3.961A    -49.55mA
3V        -3.172A    -6.982A    -181.7mA
3.24V     -7.608A    -11.14A    -3.788A
3.6V      -14.25A    -16.86A    -11A
[Ramp]
| variable   typ   min   max
dV/dt_r  1.0634/33.0059n   0.9488/41.4198n   1.1753/23.1584n
dV/dt_f  0.1964/25.9399n   0.1553/27.5201n   0.2452/24.5085n
R_load = 10.0000k
[Rising Waveform]
R_fixture= 10.0000k
V_fixture= 0.0
V_fixture_min= 0.0
V_fixture_max= 0.0
|time   V(typ)   V(min)   V(max)
0s        4.6uV      60.57uV    4.524uV
2.02ns    95.38mV    26.16mV    285.5mV
4.04ns    562.7mV    181.9mV    798.6mV
6.061ns   732.5mV    546.5mV    885.1mV
8.081ns   772.3mV    675.4mV    976.4mV
30.3ns    1.294V     1.032V     1.711V
38.38ns   1.464V     1.152V     1.874V
52.53ns   1.678V     1.351V     1.926V
76.77ns   1.742V     1.515V     1.944V
200ns     1.772V     1.581V     1.959V
[Falling Waveform]
R_fixture= 10.0000k
V_fixture= 0.0
V_fixture_min= 0.0
V_fixture_max= 0.0
|time   V(typ)   V(min)   V(max)
0s        1.773V     1.584V     1.959V
2.02ns    1.778V     1.589V     1.953V
4.04ns    1.637V     1.553V     1.733V
10.1ns    1.164V     1.104V     1.229V
26.26ns   469.9mV    475mV      477.9mV
34.34ns   247.3mV    262.1mV    241.6mV
42.42ns   130.6mV    145.2mV    122.7mV
54.55ns   51.23mV    61.09mV    45.35mV
74.75ns   12.06mV    16.05mV    9.739mV
200ns     723.7uV    1.006mV    564.3uV
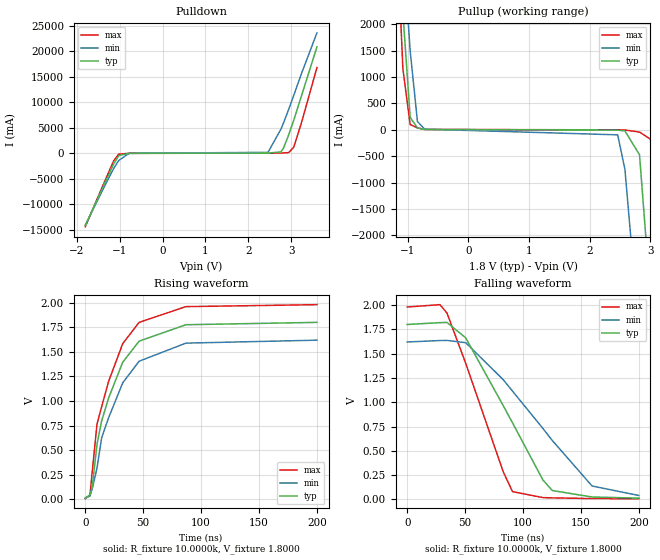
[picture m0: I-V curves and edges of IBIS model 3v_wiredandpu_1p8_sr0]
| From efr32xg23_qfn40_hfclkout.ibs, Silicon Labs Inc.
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|   Model 3v_wiredandpu_1p8_sr0
[Model]  3v_wiredandpu_1p8_sr0
Model_type Output
Polarity   Inverting
Enable   Active-Low
C_comp   1.6300pF   1.4000pF   2.7000pF
[Temperature Range]   25.0000   0.1250k   -40.0000
[Pullup Reference]   1.8000V   1.6200V   1.9800V
[Pulldown Reference]   0.0V   0.0V   0.0V
[POWER Clamp Reference]   1.8000V   1.6200V   1.9800V
[GND Clamp Reference]   0.0V   0.0V   0.0V
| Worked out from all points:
|   slope of the pulldown table from 0 to 0.27 V, typ, clamps not added: 74.9 ohm
|   slope of the pullup table from 0 to 0.27 V, typ, clamps not added: 45.3 kohm
|   rising waveform, R_fixture 10.0000k, V_fixture 1.8000: 20-80 % time 26.4ns typ, 28.1ns min, 25.4ns max; typ from 0.011 V to 1.8 V
|   falling waveform, R_fixture 10.0000k, V_fixture 1.8000: 20-80 % time 47.8ns typ, 64.1ns min, 34.2ns max; typ from 1.8 V to 0.014 V
[Pulldown]
|Voltage   I(typ)   I(min)   I(max)
-1.8V     -14.24A    -14.11A    -14.46A
-1.38V    -6.469A    -6.98A     -6.162A
-1.14V    -2.142A    -3.024A    -1.536A
-1.02V    -476.1mA   -1.44A     -185.7mA
-780mV    -29.83mA   -36.42mA   -35.11mA
2.46V     11.29mA    161mA      11.75mA
2.76V     243.1mA    4.706A     29.33mA
2.82V     965.9mA    5.915A     48.15mA
2.94V     3.567A     8.549A     112.3mA
3.06V     6.477A     11.36A     1.169A
3.24V     11.26A     15.63A     5.991A
3.6V      20.86A     23.61A     16.8A
[Pullup]
|Voltage   I(typ)   I(min)   I(max)
-1.8V     20.85A     19.71A     22.07A
-1.2V     4.976A     5.911A     4.296A
-1.08V    2.216A     3.565A     1.157A
-960mV    235.9mA    1.496A     100.8mA
-840mV    37.22mA    156.9mA    36.64mA
-720mV    7.136mA    12.83mA    7.68mA
2.46V     -4.739mA   -94.73mA   -404.8uA
2.58V     -21.18mA   -753.2mA   -2.639mA
2.82V     -472.4mA   -3.958A    -43.18mA
3V        -3.168A    -6.98A     -175.3mA
3.24V     -7.604A    -11.14A    -3.782A
3.6V      -14.24A    -16.86A    -10.99A
[Ramp]
| variable   typ   min   max
dV/dt_r  0.1949/17.0277n   0.1549/18.9539n   0.2429/15.9701n
dV/dt_f  1.0718/47.8482n   0.9474/64.0528n   1.1831/34.1702n
R_load = 10.0000k
[Rising Waveform]
R_fixture= 10.0000k
V_fixture= 1.8000
V_fixture_min= 1.6200
V_fixture_max= 1.9800
|time   V(typ)   V(min)   V(max)
0s        11.01mV    16.94mV    7.816mV
4.04ns    48.2mV     33.87mV    41.52mV
6.061ns   134.7mV    111.2mV    288.8mV
10.1ns    559.7mV    318.2mV    763.9mV
14.14ns   798.4mV    628.1mV    943.9mV
20.2ns    1.033V     832.6mV    1.202V
32.32ns   1.395V     1.185V     1.584V
46.46ns   1.609V     1.405V     1.8V
86.87ns   1.776V     1.589V     1.96V
200ns     1.8V       1.619V     1.98V
[Falling Waveform]
R_fixture= 10.0000k
V_fixture= 1.8000
V_fixture_min= 1.6200
V_fixture_max= 1.9800
|time   V(typ)   V(min)   V(max)
0s        1.8V       1.62V      1.98V
28.28ns   1.819V     1.635V     2.004V
34.34ns   1.821V     1.636V     1.918V
50.51ns   1.663V     1.613V     1.401V
82.83ns   966.9mV    1.233V     287.4mV
90.91ns   788.7mV    1.115V     80.91mV
117.2ns   200.2mV    730.3mV    19.38mV
125.3ns   91.96mV    606.6mV    16.55mV
159.6ns   25.51mV    138.7mV    9.375mV
200ns     13.72mV    40.95mV    8.209mV
